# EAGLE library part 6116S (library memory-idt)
MEMORY

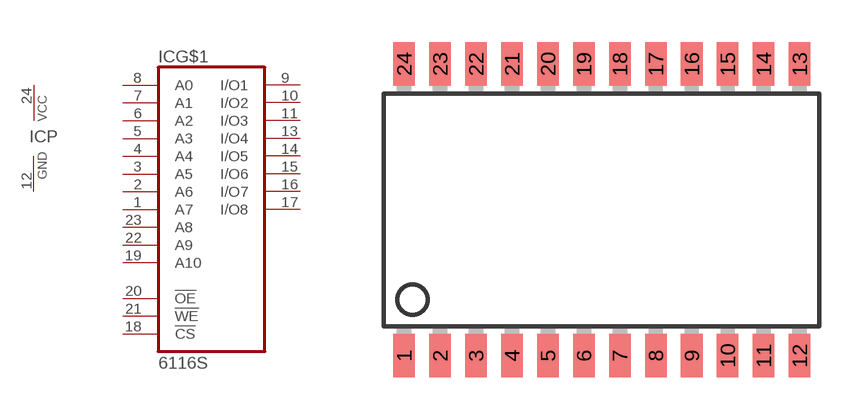
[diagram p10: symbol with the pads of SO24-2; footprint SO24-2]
Designator prefix IC; gates G$1=6116 P=VCCGND

## 6116S (OC_FARNELL: unknown; OC_NEWARK: unknown)  [SO24-2]
1  G$1:A7  in
2  G$1:A6  in
3  G$1:A5  in
4  G$1:A4  in
5  G$1:A3  in
6  G$1:A2  in
7  G$1:A1  in
8  G$1:A0  in
9  G$1:I/O1
10  G$1:I/O2
11  G$1:I/O3
12  P:GND  pwr
13  G$1:I/O4
14  G$1:I/O5
15  G$1:I/O6
16  G$1:I/O7
17  G$1:I/O8
18  G$1:!CS  in
19  G$1:A10  in
20  G$1:!OE  in
21  G$1:!WE  in
22  G$1:A9  in
23  G$1:A8  in
24  P:VCC  pwr

## Footprint SO24-2 (pad centres in mm)
Small Outline Package
smd 0.762 x 1.524: 1 -6.985,-5.156; 2 -5.715,-5.156; 3 -4.445,-5.156; 4 -3.175,-5.156; 5 -1.905,-5.156; 6 -0.635,-5.156; 7 0.635,-5.156; 8 1.905,-5.156; 9 3.175,-5.156; 10 4.445,-5.156; 11 5.715,-5.156; 12 6.985,-5.156; 13 6.985,5.156; 14 5.715,5.156; 15 4.445,5.156; 16 3.175,5.156; 17 1.905,5.156; 18 0.635,5.156; 19 -0.635,5.156; 20 -1.905,5.156; 21 -3.175,5.156; 22 -4.445,5.156; 23 -5.715,5.156; 24 -6.985,5.156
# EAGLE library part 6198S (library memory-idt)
MEMORY

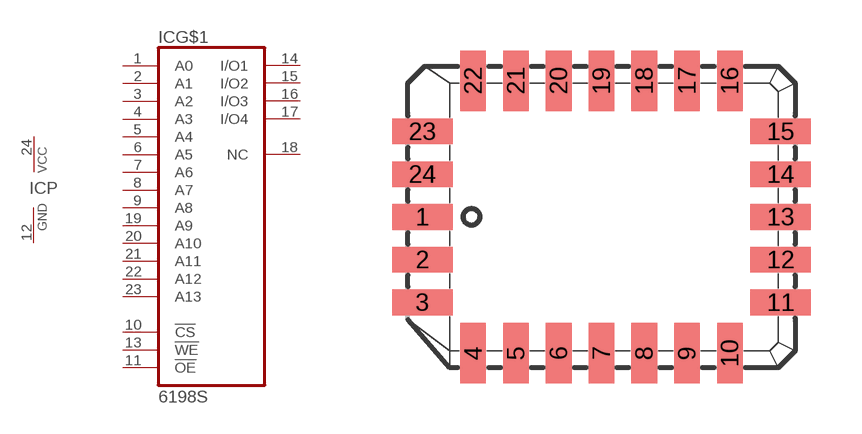
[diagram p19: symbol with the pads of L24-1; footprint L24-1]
Designator prefix IC; gates G$1=6198 P=VCCGND

## 6198S (OC_FARNELL: unknown; OC_NEWARK: unknown)  [L24-1]
1  G$1:A0  in
2  G$1:A1  in
3  G$1:A2  in
4  G$1:A3  in
5  G$1:A4  in
6  G$1:A5  in
7  G$1:A6  in
8  G$1:A7  in
9  G$1:A8  in
10  G$1:!CS  in
11  G$1:!OE  in
12  P:GND  pwr
13  G$1:!WE  in
14  G$1:I/O1
15  G$1:I/O2
16  G$1:I/O3
17  G$1:I/O4
18  G$1:NC  nc
19  G$1:A9  in
20  G$1:A10  in
21  G$1:A11  in
22  G$1:A12  in
23  G$1:A13  in
24  P:VCC  pwr

## Footprint L24-1 (pad centres in mm)
PLASTIC LEADED CHIP CARRIER rectangle
smd 1.8 x 0.76: 1 -5.32,0; 2 -5.32,-1.27; 3 -5.32,-2.54; 11 5.32,-2.54; 12 5.32,-1.27; 13 5.32,0; 14 5.32,1.27; 15 5.32,2.54; 23 -5.32,2.54; 24 -5.32,1.27
smd 0.76 x 1.8: 4 -3.81,-4.05; 5 -2.54,-4.05; 6 -1.27,-4.05; 7 0,-4.05; 8 1.27,-4.05; 9 2.54,-4.05; 10 3.81,-4.05; 16 3.81,4.05; 17 2.54,4.05; 18 1.27,4.05; 19 0,4.05; 20 -1.27,4.05; 21 -2.54,4.05; 22 -3.81,4.05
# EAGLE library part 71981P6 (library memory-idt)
MEMORY

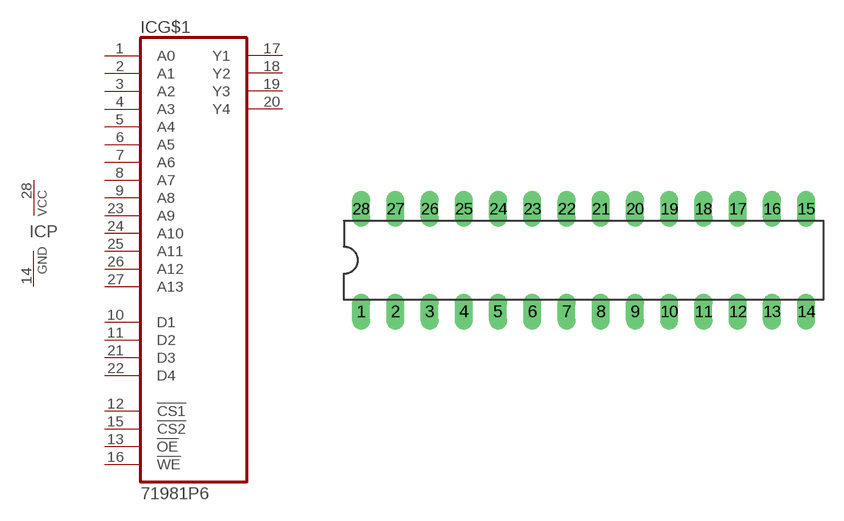
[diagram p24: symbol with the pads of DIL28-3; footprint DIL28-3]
Designator prefix IC; gates G$1=71981 P=VCCGND

## 71981P6 (OC_FARNELL: unknown; OC_NEWARK: unknown)  [DIL28-3]
1  G$1:A0  in
2  G$1:A1  in
3  G$1:A2  in
4  G$1:A3  in
5  G$1:A4  in
6  G$1:A5  in
7  G$1:A6  in
8  G$1:A7  in
9  G$1:A8  in
10  G$1:D1  in
11  G$1:D2  in
12  G$1:!CS1  in
13  G$1:!OE  in
14  P:GND  pwr
15  G$1:!CS2  in
16  G$1:!WE  in
17  G$1:Y1  out
18  G$1:Y2  out
19  G$1:Y3  out
20  G$1:Y4  out
21  G$1:D3  in
22  G$1:D4  in
23  G$1:A9  in
24  G$1:A10  in
25  G$1:A11  in
26  G$1:A12  in
27  G$1:A13  in
28  P:VCC  pwr

## Footprint DIL28-3 (pad centres in mm)
Dual In Line Package Small
drill 0.813 long: 1 -16.51,-3.81; 2 -13.97,-3.81; 3 -11.43,-3.81; 4 -8.89,-3.81; 5 -6.35,-3.81; 6 -3.81,-3.81; 7 -1.27,-3.81; 8 1.27,-3.81; 9 3.81,-3.81; 10 6.35,-3.81; 11 8.89,-3.81; 12 11.43,-3.81; 13 13.97,-3.81; 14 16.51,-3.81; 15 16.51,3.81; 16 13.97,3.81; 17 11.43,3.81; 18 8.89,3.81; 19 6.35,3.81; 20 3.81,3.81; 21 1.27,3.81; 22 -1.27,3.81; 23 -3.81,3.81; 24 -6.35,3.81; 25 -8.89,3.81; 26 -11.43,3.81; 27 -13.97,3.81; 28 -16.51,3.81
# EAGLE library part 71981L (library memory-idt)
MEMORY

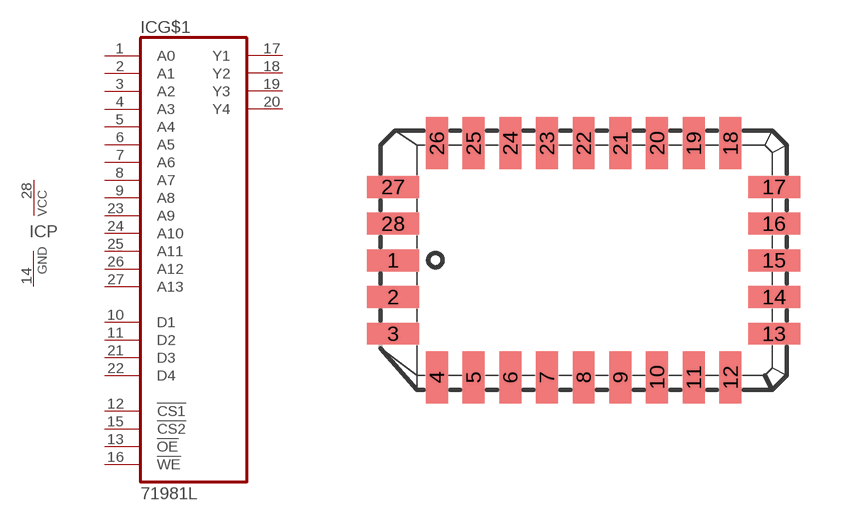
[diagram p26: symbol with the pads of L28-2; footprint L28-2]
Designator prefix IC; gates G$1=71981 P=VCCGND

## 71981L (OC_FARNELL: unknown; OC_NEWARK: unknown)  [L28-2]
1  G$1:A0  in
2  G$1:A1  in
3  G$1:A2  in
4  G$1:A3  in
5  G$1:A4  in
6  G$1:A5  in
7  G$1:A6  in
8  G$1:A7  in
9  G$1:A8  in
10  G$1:D1  in
11  G$1:D2  in
12  G$1:!CS1  in
13  G$1:!OE  in
14  P:GND  pwr
15  G$1:!CS2  in
16  G$1:!WE  in
17  G$1:Y1  out
18  G$1:Y2  out
19  G$1:Y3  out
20  G$1:Y4  out
21  G$1:D3  in
22  G$1:D4  in
23  G$1:A9  in
24  G$1:A10  in
25  G$1:A11  in
26  G$1:A12  in
27  G$1:A13  in
28  P:VCC  pwr

## Footprint L28-2 (pad centres in mm)
PLASTIC LEADED CHIP CARRIER rectangle
smd 1.8 x 0.76: 1 -6.59,0; 2 -6.59,-1.27; 3 -6.59,-2.54; 13 6.59,-2.54; 14 6.59,-1.27; 15 6.59,0; 16 6.59,1.27; 17 6.59,2.54; 27 -6.59,2.54; 28 -6.59,1.27
smd 0.76 x 1.8: 4 -5.08,-4.05; 5 -3.81,-4.05; 6 -2.54,-4.05; 7 -1.27,-4.05; 8 0,-4.05; 9 1.27,-4.05; 10 2.54,-4.05; 11 3.81,-4.05; 12 5.08,-4.05; 18 5.08,4.05; 19 3.81,4.05; 20 2.54,4.05; 21 1.27,4.05; 22 0,4.05; 23 -1.27,4.05; 24 -2.54,4.05; 25 -3.81,4.05; 26 -5.08,4.05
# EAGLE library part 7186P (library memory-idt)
MEMORY

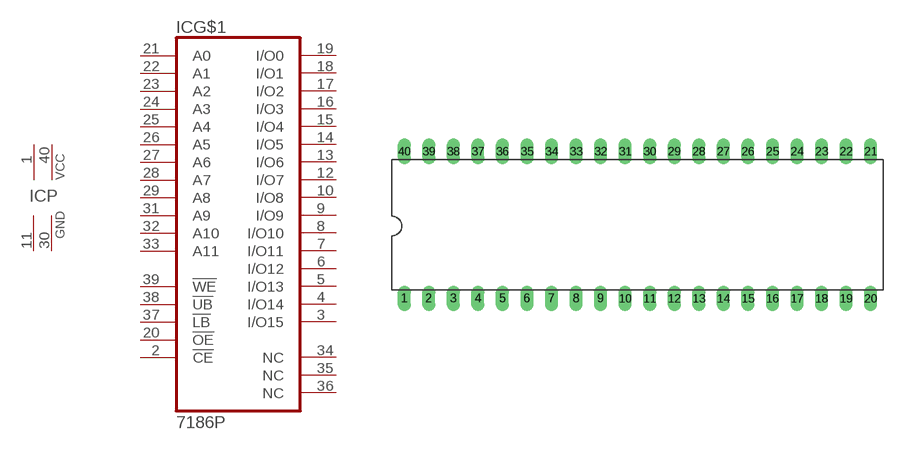
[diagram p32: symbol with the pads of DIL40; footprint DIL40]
Designator prefix IC; gates G$1=7186 P=2VCC2GND

## 7186P (OC_FARNELL: unknown; OC_NEWARK: unknown)  [DIL40]
1  P:VCC  pwr
2  G$1:!CE  in
3  G$1:I/O15
4  G$1:I/O14
5  G$1:I/O13
6  G$1:I/O12
7  G$1:I/O11
8  G$1:I/O10
9  G$1:I/O9
10  G$1:I/O8
11  P:GND  pwr
12  G$1:I/O7
13  G$1:I/O6
14  G$1:I/O5
15  G$1:I/O4
16  G$1:I/O3
17  G$1:I/O2
18  G$1:I/O1
19  G$1:I/O0
20  G$1:!OE  in
21  G$1:A0  in
22  G$1:A1  in
23  G$1:A2  in
24  G$1:A3  in
25  G$1:A4  in
26  G$1:A5  in
27  G$1:A6  in
28  G$1:A7  in
29  G$1:A8  in
30  P:GND  pwr
31  G$1:A9  in
32  G$1:A10  in
33  G$1:A11  in
34  G$1:NC  nc
35  G$1:NC  nc
36  G$1:NC  nc
37  G$1:!LB  in
38  G$1:!UB  in
39  G$1:!WE  in
40  P:VCC  pwr

## Footprint DIL40 (pad centres in mm)
Dual In Line Package
drill 0.813 long: 1 -24.13,-7.62; 2 -21.59,-7.62; 3 -19.05,-7.62; 4 -16.51,-7.62; 5 -13.97,-7.62; 6 -11.43,-7.62; 7 -8.89,-7.62; 8 -6.35,-7.62; 9 -3.81,-7.62; 10 -1.27,-7.62; 11 1.27,-7.62; 12 3.81,-7.62; 13 6.35,-7.62; 14 8.89,-7.62; 15 11.43,-7.62; 16 13.97,-7.62; 17 16.51,-7.62; 18 19.05,-7.62; 19 21.59,-7.62; 20 24.13,-7.62; 21 24.13,7.62; 22 21.59,7.62; 23 19.05,7.62; 24 16.51,7.62; 25 13.97,7.62; 26 11.43,7.62; 27 8.89,7.62; 28 6.35,7.62; 29 3.81,7.62; 30 1.27,7.62; 31 -1.27,7.62; 32 -3.81,7.62; 33 -6.35,7.62; 34 -8.89,7.62; 35 -11.43,7.62; 36 -13.97,7.62; 37 -16.51,7.62; 38 -19.05,7.62; 39 -21.59,7.62; 40 -24.13,7.62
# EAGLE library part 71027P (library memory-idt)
MEMORY

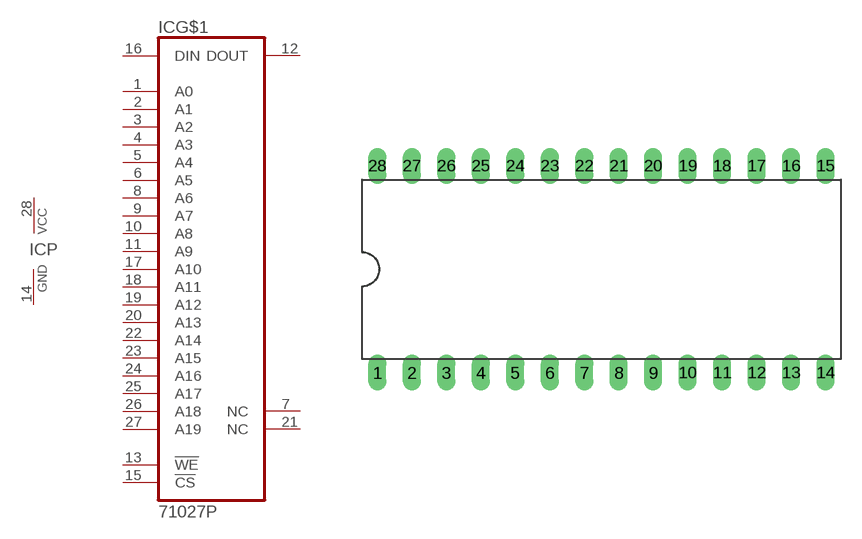
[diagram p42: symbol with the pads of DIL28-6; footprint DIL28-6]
Designator prefix IC; gates G$1=71027 P=VCCGND

## 71027P (OC_FARNELL: unknown; OC_NEWARK: unknown)  [DIL28-6]
1  G$1:A0  in
2  G$1:A1  in
3  G$1:A2  in
4  G$1:A3  in
5  G$1:A4  in
6  G$1:A5  in
7  G$1:NC  nc
8  G$1:A6  in
9  G$1:A7  in
10  G$1:A8  in
11  G$1:A9  in
12  G$1:DOUT  out
13  G$1:!WE  in
14  P:GND  pwr
15  G$1:!CS  in
16  G$1:DIN  in
17  G$1:A10  in
18  G$1:A11  in
19  G$1:A12  in
20  G$1:A13  in
21  G$1:NC  nc
22  G$1:A14  in
23  G$1:A15  in
24  G$1:A16  in
25  G$1:A17  in
26  G$1:A18  in
27  G$1:A19  in
28  P:VCC  pwr

## Footprint DIL28-6 (pad centres in mm)
Dual In Line Package 0.6 inch
drill 0.813 long: 1 -16.51,-7.62; 2 -13.97,-7.62; 3 -11.43,-7.62; 4 -8.89,-7.62; 5 -6.35,-7.62; 6 -3.81,-7.62; 7 -1.27,-7.62; 8 1.27,-7.62; 9 3.81,-7.62; 10 6.35,-7.62; 11 8.89,-7.62; 12 11.43,-7.62; 13 13.97,-7.62; 14 16.51,-7.62; 15 16.51,7.62; 16 13.97,7.62; 17 11.43,7.62; 18 8.89,7.62; 19 6.35,7.62; 20 3.81,7.62; 21 1.27,7.62; 22 -1.27,7.62; 23 -3.81,7.62; 24 -6.35,7.62; 25 -8.89,7.62; 26 -11.43,7.62; 27 -13.97,7.62; 28 -16.51,7.62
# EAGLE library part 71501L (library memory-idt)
MEMORY

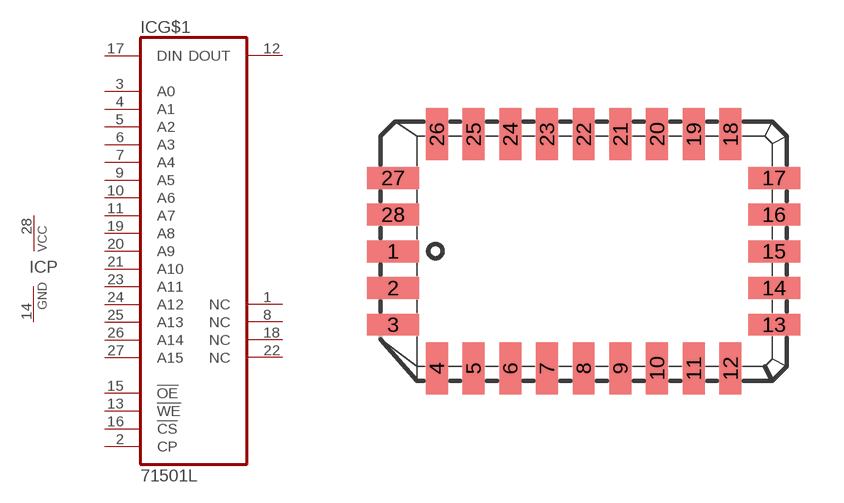
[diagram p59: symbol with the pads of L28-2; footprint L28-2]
Designator prefix IC; gates G$1=71501L P=VCCGND

## 71501L (OC_FARNELL: unknown; OC_NEWARK: unknown)  [L28-2]
1  G$1:NC  nc
2  G$1:CP  in
3  G$1:A0  in
4  G$1:A1  in
5  G$1:A2  in
6  G$1:A3  in
7  G$1:A4  in
8  G$1:NC  nc
9  G$1:A5  in
10  G$1:A6  in
11  G$1:A7  in
12  G$1:DOUT  out
13  G$1:!WE  in
14  P:GND  pwr
15  G$1:!OE  in
16  G$1:!CS  in
17  G$1:DIN  in
18  G$1:NC  nc
19  G$1:A8  in
20  G$1:A9  in
21  G$1:A10  in
22  G$1:NC  nc
23  G$1:A11  in
24  G$1:A12  in
25  G$1:A13  in
26  G$1:A14  in
27  G$1:A15  in
28  P:VCC  pwr

## Footprint L28-2 (pad centres in mm)
PLASTIC LEADED CHIP CARRIER rectangle
smd 1.8 x 0.76: 1 -6.59,0; 2 -6.59,-1.27; 3 -6.59,-2.54; 13 6.59,-2.54; 14 6.59,-1.27; 15 6.59,0; 16 6.59,1.27; 17 6.59,2.54; 27 -6.59,2.54; 28 -6.59,1.27
smd 0.76 x 1.8: 4 -5.08,-4.05; 5 -3.81,-4.05; 6 -2.54,-4.05; 7 -1.27,-4.05; 8 0,-4.05; 9 1.27,-4.05; 10 2.54,-4.05; 11 3.81,-4.05; 12 5.08,-4.05; 18 5.08,4.05; 19 3.81,4.05; 20 2.54,4.05; 21 1.27,4.05; 22 0,4.05; 23 -1.27,4.05; 24 -2.54,4.05; 25 -3.81,4.05; 26 -5.08,4.05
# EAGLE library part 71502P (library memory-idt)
MEMORY

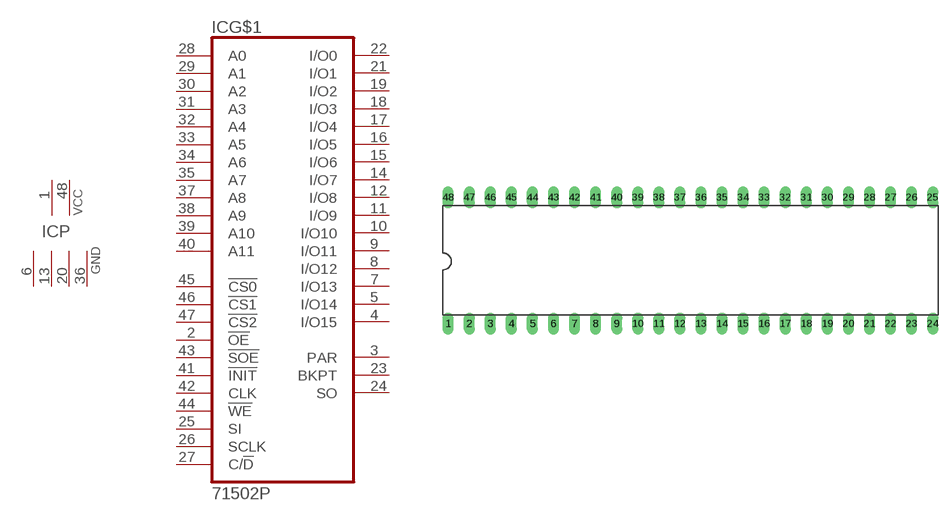
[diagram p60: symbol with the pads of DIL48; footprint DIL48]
Designator prefix IC; gates G$1=71502 P=2VCC4GND

## 71502P (OC_FARNELL: unknown; OC_NEWARK: unknown)  [DIL48]
1  P:VCC  pwr
2  G$1:!OE  in
3  G$1:PAR  out
4  G$1:I/O15
5  G$1:I/O14
6  P:GND  pwr
7  G$1:I/O13
8  G$1:I/O12
9  G$1:I/O11
10  G$1:I/O10
11  G$1:I/O9
12  G$1:I/O8
13  P:GND  pwr
14  G$1:I/O7
15  G$1:I/O6
16  G$1:I/O5
17  G$1:I/O4
18  G$1:I/O3
19  G$1:I/O2
20  P:GND  pwr
21  G$1:I/O1
22  G$1:I/O0
23  G$1:BKPT  out
24  G$1:SO  out
25  G$1:SI  in
26  G$1:SCLK  in
27  G$1:C/!D  in
28  G$1:A0  in
29  G$1:A1  in
30  G$1:A2  in
31  G$1:A3  in
32  G$1:A4  in
33  G$1:A5  in
34  G$1:A6  in
35  G$1:A7  in
36  P:GND  pwr
37  G$1:A8  in
38  G$1:A9  in
39  G$1:A10  in
40  G$1:A11  in
41  G$1:!INIT  in
42  G$1:CLK  in
43  G$1:!SOE  in
44  G$1:!WE  in
45  G$1:!CS0  in
46  G$1:!CS1  in
47  G$1:!CS2  in
48  P:VCC  pwr

## Footprint DIL48 (pad centres in mm)
Dual In Line Package
drill 0.813 long: 1 -29.21,-7.62; 2 -26.67,-7.62; 3 -24.13,-7.62; 4 -21.59,-7.62; 5 -19.05,-7.62; 6 -16.51,-7.62; 7 -13.97,-7.62; 8 -11.43,-7.62; 9 -8.89,-7.62; 10 -6.35,-7.62; 11 -3.81,-7.62; 12 -1.27,-7.62; 13 1.27,-7.62; 14 3.81,-7.62; 15 6.35,-7.62; 16 8.89,-7.62; 17 11.43,-7.62; 18 13.97,-7.62; 19 16.51,-7.62; 20 19.05,-7.62; 21 21.59,-7.62; 22 24.13,-7.62; 23 26.67,-7.62; 24 29.21,-7.62; 25 29.21,7.62; 26 26.67,7.62; 27 24.13,7.62; 28 21.59,7.62; 29 19.05,7.62; 30 16.51,7.62; 31 13.97,7.62; 32 11.43,7.62; 33 8.89,7.62; 34 6.35,7.62; 35 3.81,7.62; 36 1.27,7.62; 37 -1.27,7.62; 38 -3.81,7.62; 39 -6.35,7.62; 40 -8.89,7.62; 41 -11.43,7.62; 42 -13.97,7.62; 43 -16.51,7.62; 44 -19.05,7.62; 45 -21.59,7.62; 46 -24.13,7.62; 47 -26.67,7.62; 48 -29.21,7.62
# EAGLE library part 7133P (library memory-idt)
MEMORY

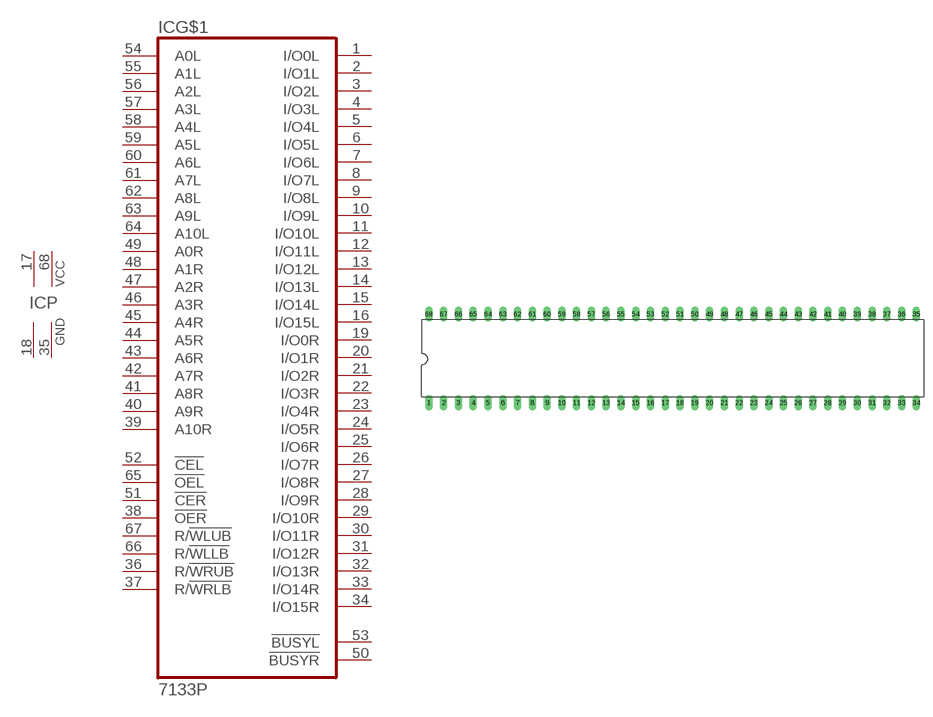
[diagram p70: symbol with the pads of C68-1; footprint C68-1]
Designator prefix IC; gates G$1=7133 P=2VCC2GND

## 7133P (OC_FARNELL: unknown; OC_NEWARK: unknown)  [C68-1]
1  G$1:I/O0L
2  G$1:I/O1L
3  G$1:I/O2L
4  G$1:I/O3L
5  G$1:I/O4L
6  G$1:I/O5L
7  G$1:I/O6L
8  G$1:I/O7L
9  G$1:I/O8L
10  G$1:I/O9L
11  G$1:I/O10L
12  G$1:I/O11L
13  G$1:I/O12L
14  G$1:I/O13L
15  G$1:I/O14L
16  G$1:I/O15L
17  P:VCC  pwr
18  P:GND  pwr
19  G$1:I/O0R
20  G$1:I/O1R
21  G$1:I/O2R
22  G$1:I/O3R
23  G$1:I/O4R
24  G$1:I/O5R
25  G$1:I/O6R
26  G$1:I/O7R
27  G$1:I/O8R
28  G$1:I/O9R
29  G$1:I/O10R
30  G$1:I/O11R
31  G$1:I/O12R
32  G$1:I/O13R
33  G$1:I/O14R
34  G$1:I/O15R
35  P:GND  pwr
36  G$1:R/!WRUB  in
37  G$1:R/!WRLB  in
38  G$1:!OER  in
39  G$1:A10R  in
40  G$1:A9R  in
41  G$1:A8R  in
42  G$1:A7R  in
43  G$1:A6R  in
44  G$1:A5R  in
45  G$1:A4R  in
46  G$1:A3R  in
47  G$1:A2R  in
48  G$1:A1R  in
49  G$1:A0R  in
50  G$1:!BUSYR  out
51  G$1:!CER  in
52  G$1:!CEL  in
53  G$1:!BUSYL  out
54  G$1:A0L  in
55  G$1:A1L  in
56  G$1:A2L  in
57  G$1:A3L  in
58  G$1:A4L  in
59  G$1:A5L  in
60  G$1:A6L  in
61  G$1:A7L  in
62  G$1:A8L  in
63  G$1:A9L  in
64  G$1:A10L  in
65  G$1:!OEL  in
66  G$1:R/!WLLB  in
67  G$1:R/!WLUB  in
68  P:VCC  pwr

## Footprint C68-1 (pad centres in mm)
Dual In Line
drill 0.813 long: 1 -41.91,-7.62; 2 -39.37,-7.62; 3 -36.83,-7.62; 4 -34.29,-7.62; 5 -31.75,-7.62; 6 -29.21,-7.62; 7 -26.67,-7.62; 8 -24.13,-7.62; 9 -21.59,-7.62; 10 -19.05,-7.62; 11 -16.51,-7.62; 12 -13.97,-7.62; 13 -11.43,-7.62; 14 -8.89,-7.62; 15 -6.35,-7.62; 16 -3.81,-7.62; 17 -1.27,-7.62; 18 1.27,-7.62; 19 3.81,-7.62; 20 6.35,-7.62; 21 8.89,-7.62; 22 11.43,-7.62; 23 13.97,-7.62; 24 16.51,-7.62; 25 19.05,-7.62; 26 21.59,-7.62; 27 24.13,-7.62; 28 26.67,-7.62; 29 29.21,-7.62; 30 31.75,-7.62; 31 34.29,-7.62; 32 36.83,-7.62; 33 39.37,-7.62; 34 41.91,-7.62; 35 41.91,7.62; 36 39.37,7.62; 37 36.83,7.62; 38 34.29,7.62; 39 31.75,7.62; 40 29.21,7.62; 41 26.67,7.62; 42 24.13,7.62; 43 21.59,7.62; 44 19.05,7.62; 45 16.51,7.62; 46 13.97,7.62; 47 11.43,7.62; 48 8.89,7.62; 49 6.35,7.62; 50 3.81,7.62; 51 1.27,7.62; 52 -1.27,7.62; 53 -3.81,7.62; 54 -6.35,7.62; 55 -8.89,7.62; 56 -11.43,7.62; 57 -13.97,7.62; 58 -16.51,7.62; 59 -19.05,7.62; 60 -21.59,7.62; 61 -24.13,7.62; 62 -26.67,7.62; 63 -29.21,7.62; 64 -31.75,7.62; 65 -34.29,7.62; 66 -36.83,7.62; 67 -39.37,7.62; 68 -41.91,7.62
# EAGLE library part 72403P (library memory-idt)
MEMORY

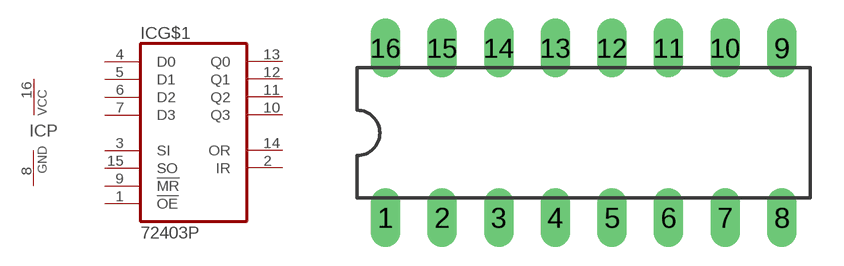
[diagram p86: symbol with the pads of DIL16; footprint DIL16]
Designator prefix IC; gates G$1=72403 P=VCCGND

## 72403P (OC_FARNELL: unknown; OC_NEWARK: unknown)  [DIL16]
1  G$1:!OE  in
2  G$1:IR  out
3  G$1:SI  in
4  G$1:D0  in
5  G$1:D1  in
6  G$1:D2  in
7  G$1:D3  in
8  P:GND  pwr
9  G$1:!MR  in
10  G$1:Q3  out
11  G$1:Q2  out
12  G$1:Q1  out
13  G$1:Q0  out
14  G$1:OR  out
15  G$1:SO  in
16  P:VCC  pwr

## Footprint DIL16 (pad centres in mm)
Dual In Line Package
drill 0.813 long: 1 -8.89,-3.81; 2 -6.35,-3.81; 3 -3.81,-3.81; 4 -1.27,-3.81; 5 1.27,-3.81; 6 3.81,-3.81; 7 6.35,-3.81; 8 8.89,-3.81; 9 8.89,3.81; 10 6.35,3.81; 11 3.81,3.81; 12 1.27,3.81; 13 -1.27,3.81; 14 -3.81,3.81; 15 -6.35,3.81; 16 -8.89,3.81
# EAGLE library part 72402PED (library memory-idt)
MEMORY

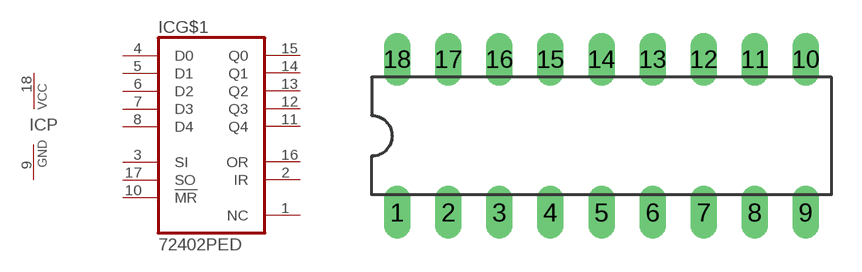
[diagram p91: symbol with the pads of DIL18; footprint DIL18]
Designator prefix IC; gates G$1=72402 P=VCCGND

## 72402PED (OC_FARNELL: unknown; OC_NEWARK: unknown)  [DIL18]
1  G$1:NC  nc
2  G$1:IR  out
3  G$1:SI  in
4  G$1:D0  in
5  G$1:D1  in
6  G$1:D2  in
7  G$1:D3  in
8  G$1:D4  in
9  P:GND  pwr
10  G$1:!MR  in
11  G$1:Q4  out
12  G$1:Q3  out
13  G$1:Q2  out
14  G$1:Q1  out
15  G$1:Q0  out
16  G$1:OR  out
17  G$1:SO  in
18  P:VCC  pwr

## Footprint DIL18 (pad centres in mm)
Dual In Line Package
drill 0.813 long: 1 -10.16,-3.81; 2 -7.62,-3.81; 3 -5.08,-3.81; 4 -2.54,-3.81; 5 0,-3.81; 6 2.54,-3.81; 7 5.08,-3.81; 8 7.62,-3.81; 9 10.16,-3.81; 10 10.16,3.81; 11 7.62,3.81; 12 5.08,3.81; 13 2.54,3.81; 14 0,3.81; 15 -2.54,3.81; 16 -5.08,3.81; 17 -7.62,3.81; 18 -10.16,3.81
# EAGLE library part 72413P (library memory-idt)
MEMORY

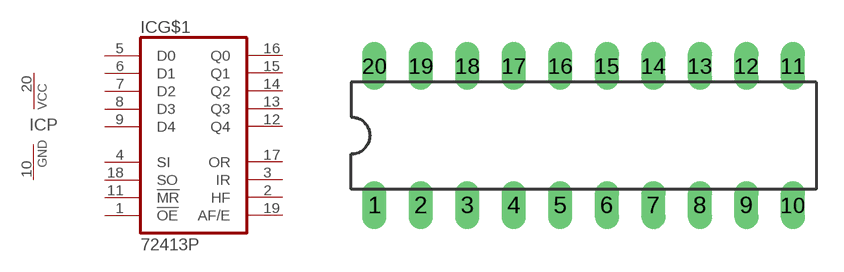
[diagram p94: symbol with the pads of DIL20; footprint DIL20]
Designator prefix IC; gates G$1=72413 P=VCCGND

## 72413P (OC_FARNELL: unknown; OC_NEWARK: unknown)  [DIL20]
1  G$1:!OE  in
2  G$1:HF  out
3  G$1:IR  out
4  G$1:SI  in
5  G$1:D0  in
6  G$1:D1  in
7  G$1:D2  in
8  G$1:D3  in
9  G$1:D4  in
10  P:GND  pwr
11  G$1:!MR  in
12  G$1:Q4  out
13  G$1:Q3  out
14  G$1:Q2  out
15  G$1:Q1  out
16  G$1:Q0  out
17  G$1:OR  out
18  G$1:SO  in
19  G$1:AF/E  out
20  P:VCC  pwr

## Footprint DIL20 (pad centres in mm)
Dual In Line Package
drill 0.813 long: 1 -11.43,-3.81; 2 -8.89,-3.81; 3 -6.35,-3.81; 4 -3.81,-3.81; 5 -1.27,-3.81; 6 1.27,-3.81; 7 3.81,-3.81; 8 6.35,-3.81; 9 8.89,-3.81; 10 11.43,-3.81; 11 11.43,3.81; 12 8.89,3.81; 13 6.35,3.81; 14 3.81,3.81; 15 1.27,3.81; 16 -1.27,3.81; 17 -3.81,3.81; 18 -6.35,3.81; 19 -8.89,3.81; 20 -11.43,3.81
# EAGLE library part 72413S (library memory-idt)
MEMORY

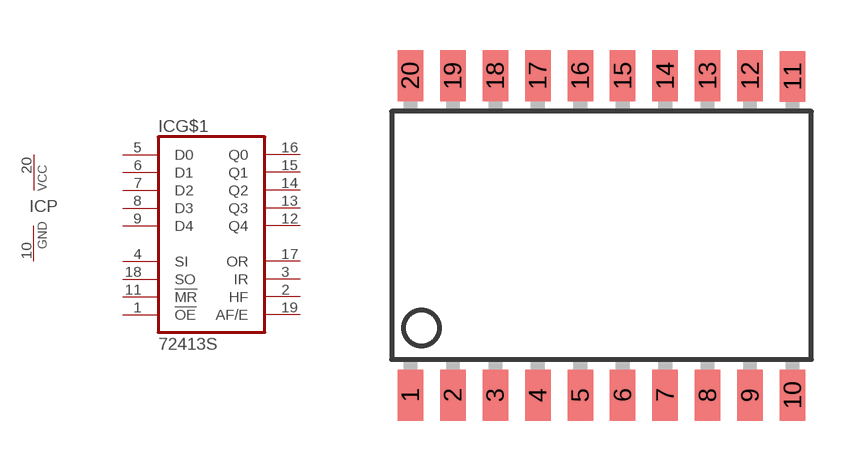
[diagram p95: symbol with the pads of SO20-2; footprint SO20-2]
Designator prefix IC; gates G$1=72413 P=VCCGND

## 72413S (OC_FARNELL: unknown; OC_NEWARK: unknown)  [SO20-2]
1  G$1:!OE  in
2  G$1:HF  out
3  G$1:IR  out
4  G$1:SI  in
5  G$1:D0  in
6  G$1:D1  in
7  G$1:D2  in
8  G$1:D3  in
9  G$1:D4  in
10  P:GND  pwr
11  G$1:!MR  in
12  G$1:Q4  out
13  G$1:Q3  out
14  G$1:Q2  out
15  G$1:Q1  out
16  G$1:Q0  out
17  G$1:OR  out
18  G$1:SO  in
19  G$1:AF/E  out
20  P:VCC  pwr

## Footprint SO20-2 (pad centres in mm)
Small Outline Package
smd 0.762 x 1.524: 1 -5.715,-4.775; 2 -4.445,-4.775; 3 -3.175,-4.775; 4 -1.905,-4.775; 5 -0.635,-4.775; 6 0.635,-4.775; 7 1.905,-4.775; 8 3.175,-4.775; 9 4.445,-4.775; 10 5.715,-4.775; 11 5.715,4.75; 12 4.445,4.775; 13 3.175,4.775; 14 1.905,4.775; 15 0.635,4.775; 16 -0.635,4.775; 17 -1.905,4.775; 18 -3.175,4.775; 19 -4.445,4.775; 20 -5.715,4.775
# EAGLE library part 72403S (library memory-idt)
MEMORY

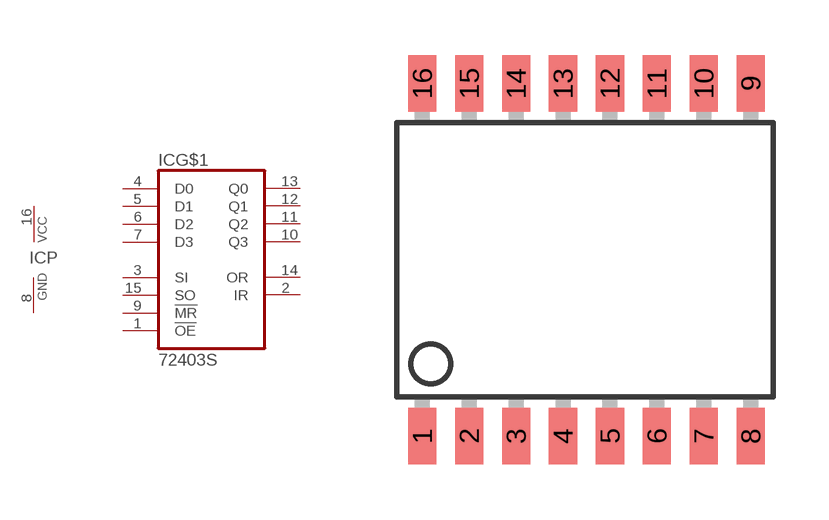
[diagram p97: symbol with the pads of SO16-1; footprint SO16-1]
Designator prefix IC; gates G$1=72403 P=VCCGND

## 72403S (OC_FARNELL: unknown; OC_NEWARK: unknown)  [SO16-1]
1  G$1:!OE  in
2  G$1:IR  out
3  G$1:SI  in
4  G$1:D0  in
5  G$1:D1  in
6  G$1:D2  in
7  G$1:D3  in
8  P:GND  pwr
9  G$1:!MR  in
10  G$1:Q3  out
11  G$1:Q2  out
12  G$1:Q1  out
13  G$1:Q0  out
14  G$1:OR  out
15  G$1:SO  in
16  P:VCC  pwr

## Footprint SO16-1 (pad centres in mm)
Small Outline Package
smd 0.762 x 1.524: 1 -4.445,-4.775; 2 -3.175,-4.775; 3 -1.905,-4.775; 4 -0.635,-4.775; 5 0.635,-4.775; 6 1.905,-4.775; 7 3.175,-4.775; 8 4.445,-4.775; 9 4.445,4.775; 10 3.175,4.775; 11 1.905,4.775; 12 0.635,4.775; 13 -0.635,4.775; 14 -1.905,4.775; 15 -3.175,4.775; 16 -4.445,4.775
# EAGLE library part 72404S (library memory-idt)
MEMORY

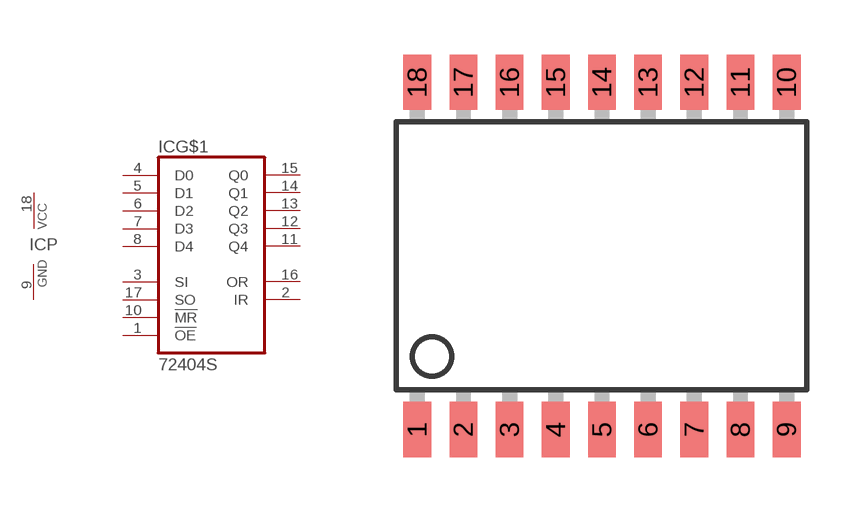
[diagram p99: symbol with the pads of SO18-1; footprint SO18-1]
Designator prefix IC; gates G$1=72404 P=VCCGND

## 72404S (OC_FARNELL: unknown; OC_NEWARK: unknown)  [SO18-1]
1  G$1:!OE  in
2  G$1:IR  out
3  G$1:SI  in
4  G$1:D0  in
5  G$1:D1  in
6  G$1:D2  in
7  G$1:D3  in
8  G$1:D4  in
9  P:GND  pwr
10  G$1:!MR  in
11  G$1:Q4  out
12  G$1:Q3  out
13  G$1:Q2  out
14  G$1:Q1  out
15  G$1:Q0  out
16  G$1:OR  out
17  G$1:SO  in
18  P:VCC  pwr

## Footprint SO18-1 (pad centres in mm)
Small Outline Package
smd 0.762 x 1.524: 1 -5.08,-4.775; 2 -3.81,-4.775; 3 -2.54,-4.775; 4 -1.27,-4.775; 5 0,-4.775; 6 1.27,-4.775; 7 2.54,-4.775; 8 3.81,-4.775; 9 5.08,-4.775; 10 5.08,4.775; 11 3.81,4.775; 12 2.54,4.775; 13 1.27,4.775; 14 0,4.775; 15 -1.27,4.775; 16 -2.54,4.775; 17 -3.81,4.775; 18 -5.08,4.775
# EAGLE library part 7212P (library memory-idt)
MEMORY

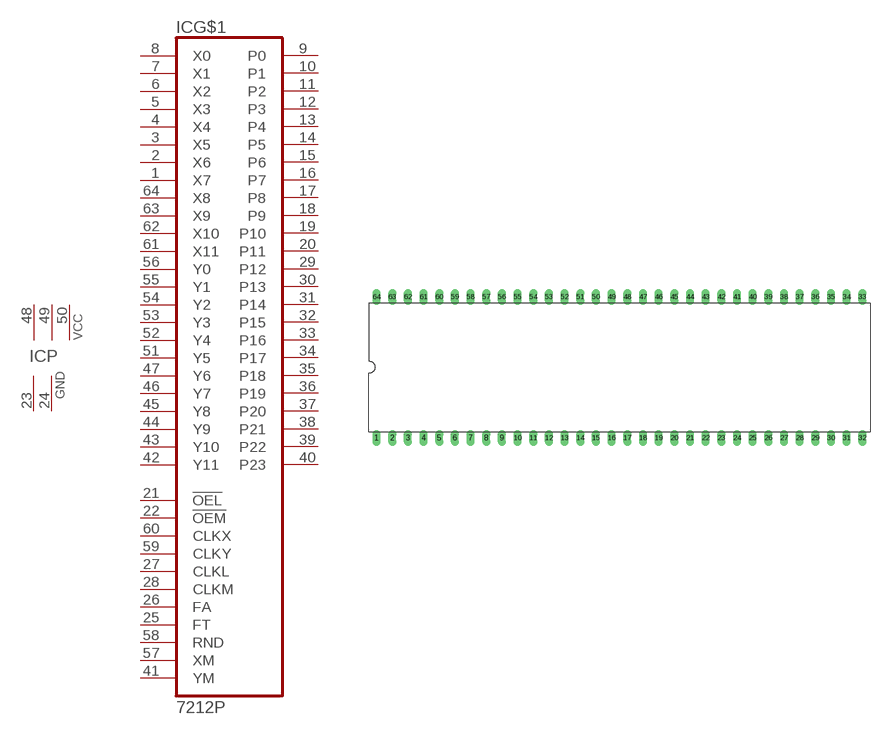
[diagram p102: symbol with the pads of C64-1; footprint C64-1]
Designator prefix IC; gates G$1=7212 P=3VCC2GND

## 7212P (OC_FARNELL: unknown; OC_NEWARK: unknown)  [C64-1]
1  G$1:X7  in
2  G$1:X6  in
3  G$1:X5  in
4  G$1:X4  in
5  G$1:X3  in
6  G$1:X2  in
7  G$1:X1  in
8  G$1:X0  in
9  G$1:P0  out
10  G$1:P1  out
11  G$1:P2  out
12  G$1:P3  out
13  G$1:P4  out
14  G$1:P5  out
15  G$1:P6  out
16  G$1:P7  out
17  G$1:P8  out
18  G$1:P9  out
19  G$1:P10  out
20  G$1:P11  out
21  G$1:!OEL  in
22  G$1:!OEM  in
23  P:GND  pwr
24  P:GND  pwr
25  G$1:FT  in
26  G$1:FA  in
27  G$1:CLKL  in
28  G$1:CLKM  in
29  G$1:P12  out
30  G$1:P13  out
31  G$1:P14  out
32  G$1:P15  out
33  G$1:P16  out
34  G$1:P17  out
35  G$1:P18  out
36  G$1:P19  out
37  G$1:P20  out
38  G$1:P21  out
39  G$1:P22  out
40  G$1:P23  out
41  G$1:YM  in
42  G$1:Y11  in
43  G$1:Y10  in
44  G$1:Y9  in
45  G$1:Y8  in
46  G$1:Y7  in
47  G$1:Y6  in
48  P:VCC  pwr
49  P:VCC  pwr
50  P:VCC  pwr
51  G$1:Y5  in
52  G$1:Y4  in
53  G$1:Y3  in
54  G$1:Y2  in
55  G$1:Y1  in
56  G$1:Y0  in
57  G$1:XM  in
58  G$1:RND  in
59  G$1:CLKY  in
60  G$1:CLKX  in
61  G$1:X11  in
62  G$1:X10  in
63  G$1:X9  in
64  G$1:X8  in

## Footprint C64-1 (pad centres in mm)
Dual In Line
drill 0.813 long: 1 -39.37,-11.43; 2 -36.83,-11.43; 3 -34.29,-11.43; 4 -31.75,-11.43; 5 -29.21,-11.43; 6 -26.67,-11.43; 7 -24.13,-11.43; 8 -21.59,-11.43; 9 -19.05,-11.43; 10 -16.51,-11.43; 11 -13.97,-11.43; 12 -11.43,-11.43; 13 -8.89,-11.43; 14 -6.35,-11.43; 15 -3.81,-11.43; 16 -1.27,-11.43; 17 1.27,-11.43; 18 3.81,-11.43; 19 6.35,-11.43; 20 8.89,-11.43; 21 11.43,-11.43; 22 13.97,-11.43; 23 16.51,-11.43; 24 19.05,-11.43; 25 21.59,-11.43; 26 24.13,-11.43; 27 26.67,-11.43; 28 29.21,-11.43; 29 31.75,-11.43; 30 34.29,-11.43; 31 36.83,-11.43; 32 39.37,-11.43; 33 39.37,11.43; 34 36.83,11.43; 35 34.29,11.43; 36 31.75,11.43; 37 29.21,11.43; 38 26.67,11.43; 39 24.13,11.43; 40 21.59,11.43; 41 19.05,11.43; 42 16.51,11.43; 43 13.97,11.43; 44 11.43,11.43; 45 8.89,11.43; 46 6.35,11.43; 47 3.81,11.43; 48 1.27,11.43; 49 -1.27,11.43; 50 -3.81,11.43; 51 -6.35,11.43; 52 -8.89,11.43; 53 -11.43,11.43; 54 -13.97,11.43; 55 -16.51,11.43; 56 -19.05,11.43; 57 -21.59,11.43; 58 -24.13,11.43; 59 -26.67,11.43; 60 -29.21,11.43; 61 -31.75,11.43; 62 -34.29,11.43; 63 -36.83,11.43; 64 -39.37,11.43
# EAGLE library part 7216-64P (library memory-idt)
MEMORY

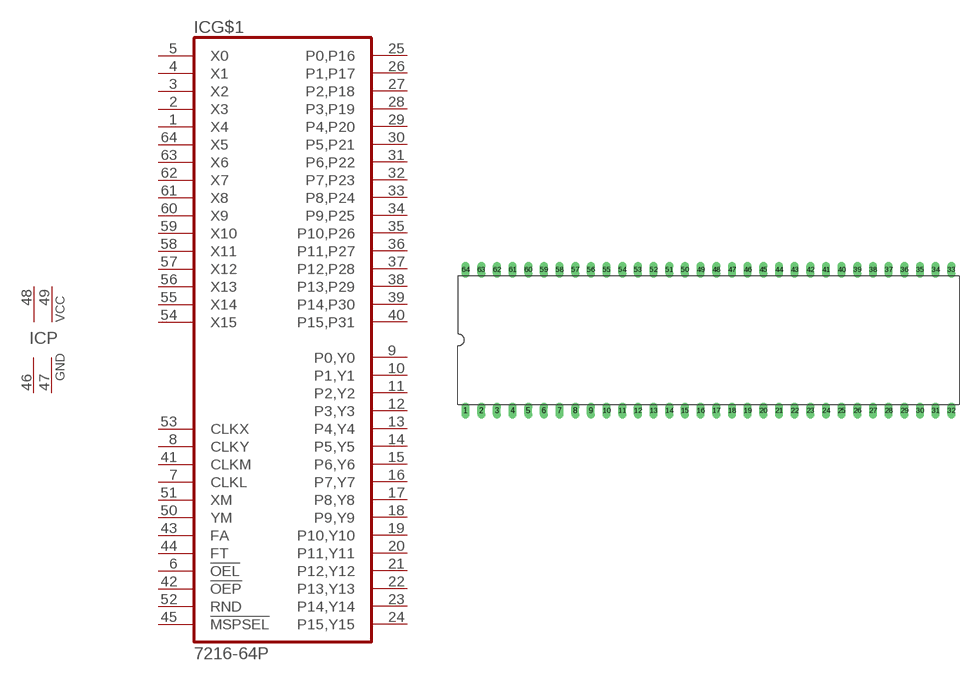
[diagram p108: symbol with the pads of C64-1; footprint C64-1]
Designator prefix IC; gates G$1=7216-64 P=2VCC2GND

## 7216-64P (OC_FARNELL: unknown; OC_NEWARK: unknown)  [C64-1]
1  G$1:X4  in
2  G$1:X3  in
3  G$1:X2  in
4  G$1:X1  in
5  G$1:X0  in
6  G$1:!OEL  in
7  G$1:CLKL  in
8  G$1:CLKY  in
9  G$1:P0,Y0
10  G$1:P1,Y1
11  G$1:P2,Y2
12  G$1:P3,Y3
13  G$1:P4,Y4
14  G$1:P5,Y5
15  G$1:P6,Y6
16  G$1:P7,Y7
17  G$1:P8,Y8
18  G$1:P9,Y9
19  G$1:P10,Y10
20  G$1:P11,Y11
21  G$1:P12,Y12
22  G$1:P13,Y13
23  G$1:P14,Y14
24  G$1:P15,Y15
25  G$1:P0,P16  out
26  G$1:P1,P17  out
27  G$1:P2,P18  out
28  G$1:P3,P19  out
29  G$1:P4,P20  out
30  G$1:P5,P21  out
31  G$1:P6,P22  out
32  G$1:P7,P23  out
33  G$1:P8,P24  out
34  G$1:P9,P25  out
35  G$1:P10,P26  out
36  G$1:P11,P27  out
37  G$1:P12,P28  out
38  G$1:P13,P29  out
39  G$1:P14,P30  out
40  G$1:P15,P31  out
41  G$1:CLKM  in
42  G$1:!OEP  in
43  G$1:FA  in
44  G$1:FT  in
45  G$1:!MSPSEL  in
46  P:GND  pwr
47  P:GND  pwr
48  P:VCC  pwr
49  P:VCC  pwr
50  G$1:YM  in
51  G$1:XM  in
52  G$1:RND  in
53  G$1:CLKX  in
54  G$1:X15  in
55  G$1:X14  in
56  G$1:X13  in
57  G$1:X12  in
58  G$1:X11  in
59  G$1:X10  in
60  G$1:X9  in
61  G$1:X8  in
62  G$1:X7  in
63  G$1:X6  in
64  G$1:X5  in

## Footprint C64-1 (pad centres in mm)
Dual In Line
drill 0.813 long: 1 -39.37,-11.43; 2 -36.83,-11.43; 3 -34.29,-11.43; 4 -31.75,-11.43; 5 -29.21,-11.43; 6 -26.67,-11.43; 7 -24.13,-11.43; 8 -21.59,-11.43; 9 -19.05,-11.43; 10 -16.51,-11.43; 11 -13.97,-11.43; 12 -11.43,-11.43; 13 -8.89,-11.43; 14 -6.35,-11.43; 15 -3.81,-11.43; 16 -1.27,-11.43; 17 1.27,-11.43; 18 3.81,-11.43; 19 6.35,-11.43; 20 8.89,-11.43; 21 11.43,-11.43; 22 13.97,-11.43; 23 16.51,-11.43; 24 19.05,-11.43; 25 21.59,-11.43; 26 24.13,-11.43; 27 26.67,-11.43; 28 29.21,-11.43; 29 31.75,-11.43; 30 34.29,-11.43; 31 36.83,-11.43; 32 39.37,-11.43; 33 39.37,11.43; 34 36.83,11.43; 35 34.29,11.43; 36 31.75,11.43; 37 29.21,11.43; 38 26.67,11.43; 39 24.13,11.43; 40 21.59,11.43; 41 19.05,11.43; 42 16.51,11.43; 43 13.97,11.43; 44 11.43,11.43; 45 8.89,11.43; 46 6.35,11.43; 47 3.81,11.43; 48 1.27,11.43; 49 -1.27,11.43; 50 -3.81,11.43; 51 -6.35,11.43; 52 -8.89,11.43; 53 -11.43,11.43; 54 -13.97,11.43; 55 -16.51,11.43; 56 -19.05,11.43; 57 -21.59,11.43; 58 -24.13,11.43; 59 -26.67,11.43; 60 -29.21,11.43; 61 -31.75,11.43; 62 -34.29,11.43; 63 -36.83,11.43; 64 -39.37,11.43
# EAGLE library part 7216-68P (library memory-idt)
MEMORY

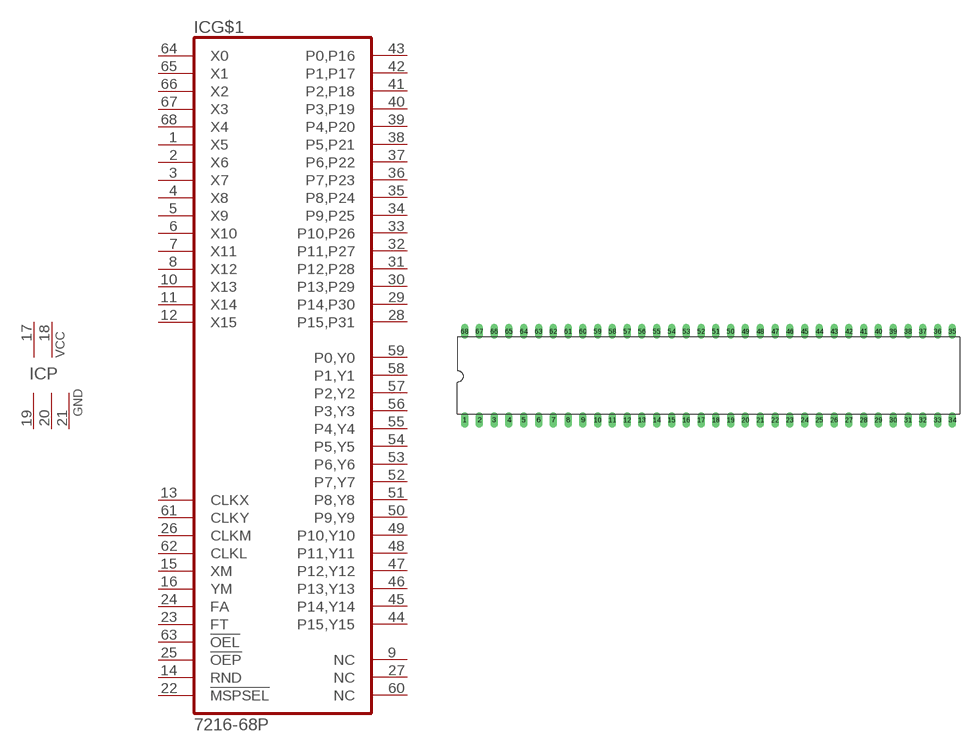
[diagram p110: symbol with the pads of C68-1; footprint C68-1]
Designator prefix IC; gates G$1=7216-68 P=2VCC3GND

## 7216-68P (OC_FARNELL: unknown; OC_NEWARK: unknown)  [C68-1]
1  G$1:X5  in
2  G$1:X6  in
3  G$1:X7  in
4  G$1:X8  in
5  G$1:X9  in
6  G$1:X10  in
7  G$1:X11  in
8  G$1:X12  in
9  G$1:NC  nc
10  G$1:X13  in
11  G$1:X14  in
12  G$1:X15  in
13  G$1:CLKX  in
14  G$1:RND  in
15  G$1:XM  in
16  G$1:YM  in
17  P:VCC  pwr
18  P:VCC  pwr
19  P:GND  pwr
20  P:GND  pwr
21  P:GND  pwr
22  G$1:!MSPSEL  in
23  G$1:FT  in
24  G$1:FA  in
25  G$1:!OEP  in
26  G$1:CLKM  in
27  G$1:NC  nc
28  G$1:P15,P31  out
29  G$1:P14,P30  out
30  G$1:P13,P29  out
31  G$1:P12,P28  out
32  G$1:P11,P27  out
33  G$1:P10,P26  out
34  G$1:P9,P25  out
35  G$1:P8,P24  out
36  G$1:P7,P23  out
37  G$1:P6,P22  out
38  G$1:P5,P21  out
39  G$1:P4,P20  out
40  G$1:P3,P19  out
41  G$1:P2,P18  out
42  G$1:P1,P17  out
43  G$1:P0,P16  out
44  G$1:P15,Y15
45  G$1:P14,Y14
46  G$1:P13,Y13
47  G$1:P12,Y12
48  G$1:P11,Y11
49  G$1:P10,Y10
50  G$1:P9,Y9
51  G$1:P8,Y8
52  G$1:P7,Y7
53  G$1:P6,Y6
54  G$1:P5,Y5
55  G$1:P4,Y4
56  G$1:P3,Y3
57  G$1:P2,Y2
58  G$1:P1,Y1
59  G$1:P0,Y0
60  G$1:NC  nc
61  G$1:CLKY  in
62  G$1:CLKL  in
63  G$1:!OEL  in
64  G$1:X0  in
65  G$1:X1  in
66  G$1:X2  in
67  G$1:X3  in
68  G$1:X4  in

## Footprint C68-1 (pad centres in mm)
Dual In Line
drill 0.813 long: 1 -41.91,-7.62; 2 -39.37,-7.62; 3 -36.83,-7.62; 4 -34.29,-7.62; 5 -31.75,-7.62; 6 -29.21,-7.62; 7 -26.67,-7.62; 8 -24.13,-7.62; 9 -21.59,-7.62; 10 -19.05,-7.62; 11 -16.51,-7.62; 12 -13.97,-7.62; 13 -11.43,-7.62; 14 -8.89,-7.62; 15 -6.35,-7.62; 16 -3.81,-7.62; 17 -1.27,-7.62; 18 1.27,-7.62; 19 3.81,-7.62; 20 6.35,-7.62; 21 8.89,-7.62; 22 11.43,-7.62; 23 13.97,-7.62; 24 16.51,-7.62; 25 19.05,-7.62; 26 21.59,-7.62; 27 24.13,-7.62; 28 26.67,-7.62; 29 29.21,-7.62; 30 31.75,-7.62; 31 34.29,-7.62; 32 36.83,-7.62; 33 39.37,-7.62; 34 41.91,-7.62; 35 41.91,7.62; 36 39.37,7.62; 37 36.83,7.62; 38 34.29,7.62; 39 31.75,7.62; 40 29.21,7.62; 41 26.67,7.62; 42 24.13,7.62; 43 21.59,7.62; 44 19.05,7.62; 45 16.51,7.62; 46 13.97,7.62; 47 11.43,7.62; 48 8.89,7.62; 49 6.35,7.62; 50 3.81,7.62; 51 1.27,7.62; 52 -1.27,7.62; 53 -3.81,7.62; 54 -6.35,7.62; 55 -8.89,7.62; 56 -11.43,7.62; 57 -13.97,7.62; 58 -16.51,7.62; 59 -19.05,7.62; 60 -21.59,7.62; 61 -24.13,7.62; 62 -26.67,7.62; 63 -29.21,7.62; 64 -31.75,7.62; 65 -34.29,7.62; 66 -36.83,7.62; 67 -39.37,7.62; 68 -41.91,7.62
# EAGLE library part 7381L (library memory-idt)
MEMORY

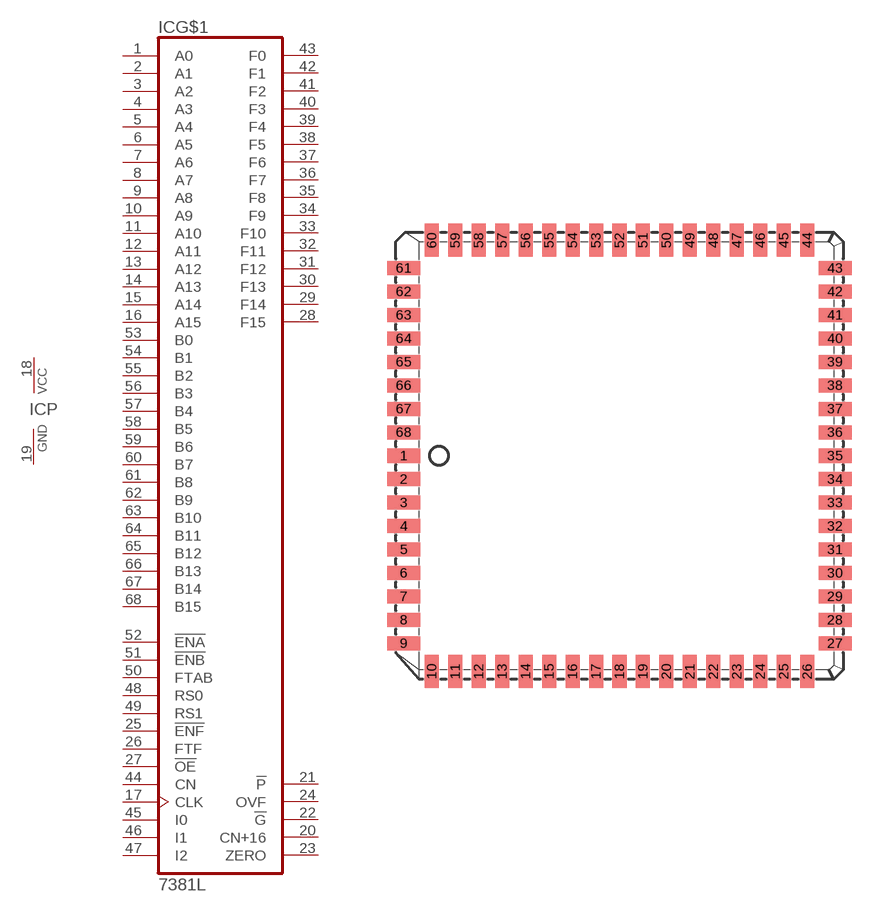
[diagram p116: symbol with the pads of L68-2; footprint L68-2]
Designator prefix IC; gates G$1=7381 P=VCCGND

## 7381L (OC_FARNELL: unknown; OC_NEWARK: unknown)  [L68-2]
1  G$1:A0  in
2  G$1:A1  in
3  G$1:A2  in
4  G$1:A3  in
5  G$1:A4  in
6  G$1:A5  in
7  G$1:A6  in
8  G$1:A7  in
9  G$1:A8  in
10  G$1:A9  in
11  G$1:A10  in
12  G$1:A11  in
13  G$1:A12  in
14  G$1:A13  in
15  G$1:A14  in
16  G$1:A15  in
17  G$1:CLK  in
18  P:VCC  pwr
19  P:GND  pwr
20  G$1:CN+16  out
21  G$1:!P  out
22  G$1:!G  out
23  G$1:ZERO  out
24  G$1:OVF  out
25  G$1:!ENF  in
26  G$1:FTF  in
27  G$1:!OE  in
28  G$1:F15  out
29  G$1:F14  out
30  G$1:F13  out
31  G$1:F12  out
32  G$1:F11  out
33  G$1:F10  out
34  G$1:F9  out
35  G$1:F8  out
36  G$1:F7  out
37  G$1:F6  out
38  G$1:F5  out
39  G$1:F4  out
40  G$1:F3  out
41  G$1:F2  out
42  G$1:F1  out
43  G$1:F0  out
44  G$1:CN  in
45  G$1:I0  in
46  G$1:I1  in
47  G$1:I2  in
48  G$1:RS0  in
49  G$1:RS1  in
50  G$1:FTAB  in
51  G$1:!ENB  in
52  G$1:!ENA  in
53  G$1:B0  in
54  G$1:B1  in
55  G$1:B2  in
56  G$1:B3  in
57  G$1:B4  in
58  G$1:B5  in
59  G$1:B6  in
60  G$1:B7  in
61  G$1:B8  in
62  G$1:B9  in
63  G$1:B10  in
64  G$1:B11  in
65  G$1:B12  in
66  G$1:B13  in
67  G$1:B14  in
68  G$1:B15  in

## Footprint L68-2 (pad centres in mm)
PLASTIC LEADED CHIP CARRIER square
smd 1.8 x 0.76: 1 -11.67,0; 2 -11.67,-1.27; 3 -11.67,-2.54; 4 -11.67,-3.81; 5 -11.67,-5.08; 6 -11.67,-6.35; 7 -11.67,-7.62; 8 -11.67,-8.89; 9 -11.67,-10.16; 27 11.67,-10.16; 28 11.67,-8.89; 29 11.67,-7.62; 30 11.67,-6.35; 31 11.67,-5.08; 32 11.67,-3.81; 33 11.67,-2.54; 34 11.67,-1.27; 35 11.67,0; 36 11.67,1.27; 37 11.67,2.54; 38 11.67,3.81; 39 11.67,5.08; 40 11.67,6.35; 41 11.67,7.62; 42 11.67,8.89; 43 11.67,10.16; 61 -11.67,10.16; 62 -11.67,8.89; 63 -11.67,7.62; 64 -11.67,6.35; 65 -11.67,5.08; 66 -11.67,3.81; 67 -11.67,2.54; 68 -11.67,1.27
smd 0.76 x 1.8: 10 -10.16,-11.67; 11 -8.89,-11.67; 12 -7.62,-11.67; 13 -6.35,-11.67; 14 -5.08,-11.67; 15 -3.81,-11.67; 16 -2.54,-11.67; 17 -1.27,-11.67; 18 0,-11.67; 19 1.27,-11.67; 20 2.54,-11.67; 21 3.81,-11.67; 22 5.08,-11.67; 23 6.35,-11.67; 24 7.62,-11.67; 25 8.89,-11.67; 26 10.16,-11.67; 44 10.16,11.67; 45 8.89,11.67; 46 7.62,11.67; 47 6.35,11.67; 48 5.08,11.67; 49 3.81,11.67; 50 2.54,11.67; 51 1.27,11.67; 52 0,11.67; 53 -1.27,11.67; 54 -2.54,11.67; 55 -3.81,11.67; 56 -5.08,11.67; 57 -6.35,11.67; 58 -7.62,11.67; 59 -8.89,11.67; 60 -10.16,11.67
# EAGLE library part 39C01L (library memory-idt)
MEMORY

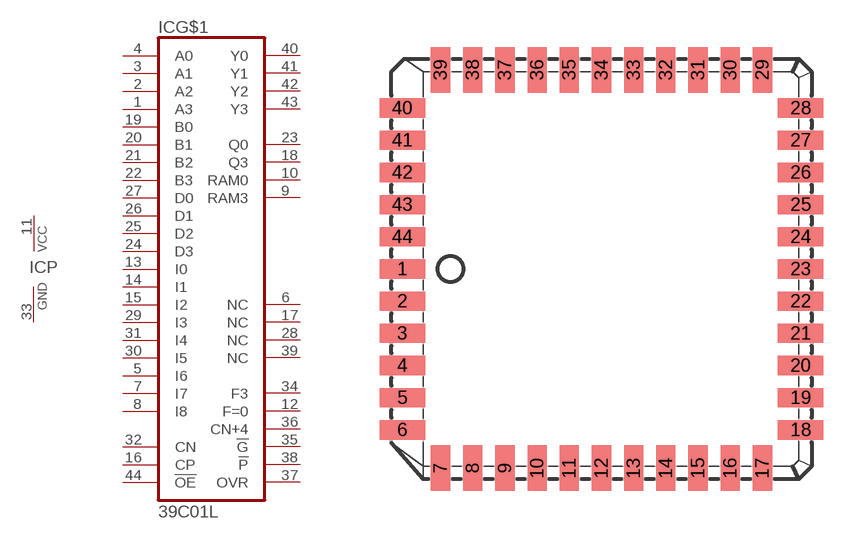
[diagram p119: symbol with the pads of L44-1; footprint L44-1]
Designator prefix IC; gates G$1=39C01L P=VCCGND

## 39C01L (OC_FARNELL: unknown; OC_NEWARK: unknown)  [L44-1]
1  G$1:A3  in
2  G$1:A2  in
3  G$1:A1  in
4  G$1:A0  in
5  G$1:I6  in
6  G$1:NC  nc
7  G$1:I7  in
8  G$1:I8  in
9  G$1:RAM3
10  G$1:RAM0
11  P:VCC  pwr
12  G$1:F=0  out
13  G$1:I0  in
14  G$1:I1  in
15  G$1:I2  in
16  G$1:CP  in
17  G$1:NC  nc
18  G$1:Q3
19  G$1:B0  in
20  G$1:B1  in
21  G$1:B2  in
22  G$1:B3  in
23  G$1:Q0
24  G$1:D3  in
25  G$1:D2  in
26  G$1:D1  in
27  G$1:D0  in
28  G$1:NC  nc
29  G$1:I3  in
30  G$1:I5  in
31  G$1:I4  in
32  G$1:CN  in
33  P:GND  pwr
34  G$1:F3  out
35  G$1:!G  out
36  G$1:CN+4  out
37  G$1:OVR  out
38  G$1:!P  out
39  G$1:NC  nc
40  G$1:Y0  out
41  G$1:Y1  out
42  G$1:Y2  out
43  G$1:Y3  out
44  G$1:!OE  in

## Footprint L44-1 (pad centres in mm)
PLASTIC LEADED CHIP CARRIER square
smd 1.8 x 0.76: 1 -7.86,0; 2 -7.86,-1.27; 3 -7.86,-2.54; 4 -7.86,-3.81; 5 -7.86,-5.08; 6 -7.86,-6.35; 18 7.86,-6.35; 19 7.86,-5.08; 20 7.86,-3.81; 21 7.86,-2.54; 22 7.86,-1.27; 23 7.86,0; 24 7.86,1.27; 25 7.86,2.54; 26 7.86,3.81; 27 7.86,5.08; 28 7.86,6.35; 40 -7.86,6.35; 41 -7.86,5.08; 42 -7.86,3.81; 43 -7.86,2.54; 44 -7.86,1.27
smd 0.76 x 1.8: 7 -6.35,-7.86; 8 -5.08,-7.86; 9 -3.81,-7.86; 10 -2.54,-7.86; 11 -1.27,-7.86; 12 0,-7.86; 13 1.27,-7.86; 14 2.54,-7.86; 15 3.81,-7.86; 16 5.08,-7.86; 17 6.35,-7.86; 29 6.35,7.86; 30 5.08,7.86; 31 3.81,7.86; 32 2.54,7.86; 33 1.27,7.86; 34 0,7.86; 35 -1.27,7.86; 36 -2.54,7.86; 37 -3.81,7.86; 38 -5.08,7.86; 39 -6.35,7.86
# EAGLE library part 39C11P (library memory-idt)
MEMORY

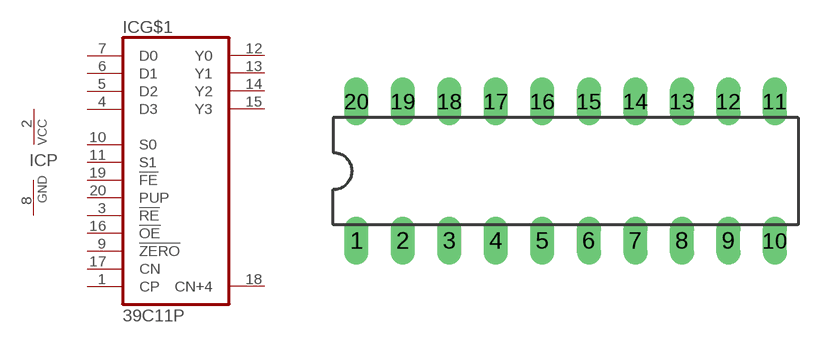
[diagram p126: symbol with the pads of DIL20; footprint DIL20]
Designator prefix IC; gates G$1=39C11 P=VCCGND

## 39C11P (OC_FARNELL: unknown; OC_NEWARK: unknown)  [DIL20]
1  G$1:CP  in
2  P:VCC  pwr
3  G$1:!RE  in
4  G$1:D3  in
5  G$1:D2  in
6  G$1:D1  in
7  G$1:D0  in
8  P:GND  pwr
9  G$1:!ZERO  in
10  G$1:S0  in
11  G$1:S1  in
12  G$1:Y0  out
13  G$1:Y1  out
14  G$1:Y2  out
15  G$1:Y3  out
16  G$1:!OE  in
17  G$1:CN  in
18  G$1:CN+4  out
19  G$1:!FE  in
20  G$1:PUP  in

## Footprint DIL20 (pad centres in mm)
Dual In Line Package
drill 0.813 long: 1 -11.43,-3.81; 2 -8.89,-3.81; 3 -6.35,-3.81; 4 -3.81,-3.81; 5 -1.27,-3.81; 6 1.27,-3.81; 7 3.81,-3.81; 8 6.35,-3.81; 9 8.89,-3.81; 10 11.43,-3.81; 11 11.43,3.81; 12 8.89,3.81; 13 6.35,3.81; 14 3.81,3.81; 15 1.27,3.81; 16 -1.27,3.81; 17 -3.81,3.81; 18 -6.35,3.81; 19 -8.89,3.81; 20 -11.43,3.81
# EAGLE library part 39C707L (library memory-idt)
MEMORY

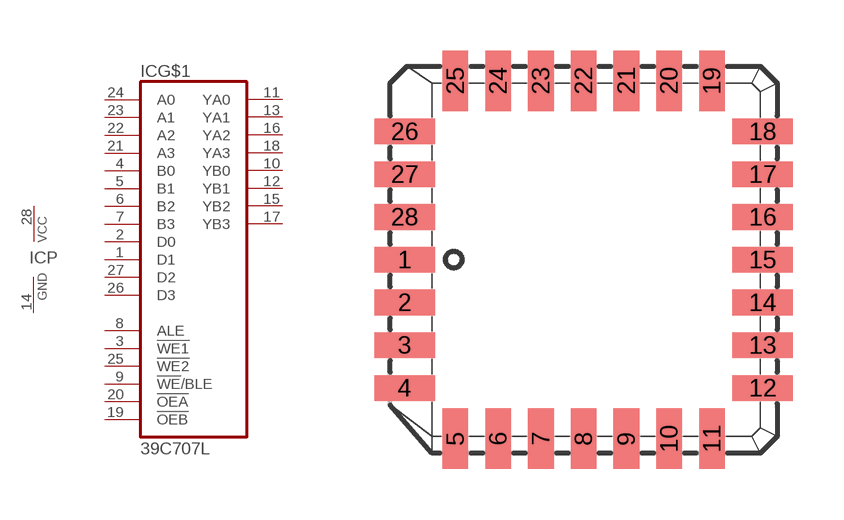
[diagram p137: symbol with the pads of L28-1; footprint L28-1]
Designator prefix IC; gates G$1=39C707 P=VCCGND

## 39C707L (OC_FARNELL: unknown; OC_NEWARK: unknown)  [L28-1]
1  G$1:D1  in
2  G$1:D0  in
3  G$1:!WE1  in
4  G$1:B0  in
5  G$1:B1  in
6  G$1:B2  in
7  G$1:B3  in
8  G$1:ALE  in
9  G$1:!WE!/BLE  in
10  G$1:YB0  out
11  G$1:YA0  out
12  G$1:YB1  out
13  G$1:YA1  out
14  P:GND  pwr
15  G$1:YB2  out
16  G$1:YA2  out
17  G$1:YB3  out
18  G$1:YA3  out
19  G$1:!OEB  in
20  G$1:!OEA  in
21  G$1:A3  in
22  G$1:A2  in
23  G$1:A1  in
24  G$1:A0  in
25  G$1:!WE2  in
26  G$1:D3  in
27  G$1:D2  in
28  P:VCC  pwr

## Footprint L28-1 (pad centres in mm)
PLASTIC LEADED CHIP CARRIER square
smd 1.8 x 0.76: 1 -5.32,0; 2 -5.32,-1.27; 3 -5.32,-2.54; 4 -5.32,-3.81; 12 5.32,-3.81; 13 5.32,-2.54; 14 5.32,-1.27; 15 5.32,0; 16 5.32,1.27; 17 5.32,2.54; 18 5.32,3.81; 26 -5.32,3.81; 27 -5.32,2.54; 28 -5.32,1.27
smd 0.76 x 1.8: 5 -3.81,-5.32; 6 -2.54,-5.32; 7 -1.27,-5.32; 8 0,-5.32; 9 1.27,-5.32; 10 2.54,-5.32; 11 3.81,-5.32; 19 3.81,5.32; 20 2.54,5.32; 21 1.27,5.32; 22 0,5.32; 23 -1.27,5.32; 24 -2.54,5.32; 25 -3.81,5.32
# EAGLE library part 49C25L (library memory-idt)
MEMORY

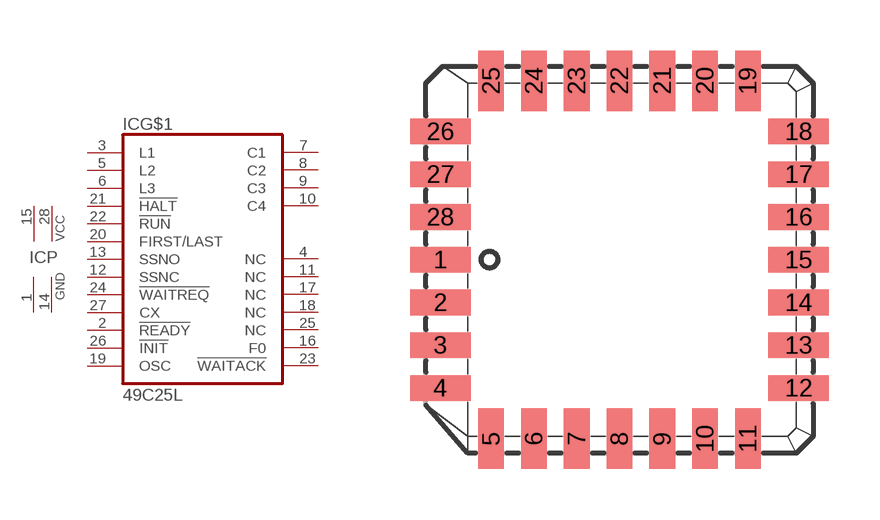
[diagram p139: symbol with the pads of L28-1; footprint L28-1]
Designator prefix IC; gates G$1=49C25L P=2VCC2GND

## 49C25L (OC_FARNELL: unknown; OC_NEWARK: unknown)  [L28-1]
1  P:GND  pwr
2  G$1:!READY  in
3  G$1:L1  in
4  G$1:NC  nc
5  G$1:L2  in
6  G$1:L3  in
7  G$1:C1  out
8  G$1:C2  out
9  G$1:C3  out
10  G$1:C4  out
11  G$1:NC  nc
12  G$1:SSNC  in
13  G$1:SSNO  in
14  P:GND  pwr
15  P:VCC  pwr
16  G$1:F0  out
17  G$1:NC  nc
18  G$1:NC  nc
19  G$1:OSC  in
20  G$1:FIRST/LAST  in
21  G$1:!HALT  in
22  G$1:!RUN  in
23  G$1:!WAITACK  out
24  G$1:!WAITREQ  in
25  G$1:NC  nc
26  G$1:!INIT  in
27  G$1:CX  in
28  P:VCC  pwr

## Footprint L28-1 (pad centres in mm)
PLASTIC LEADED CHIP CARRIER square
smd 1.8 x 0.76: 1 -5.32,0; 2 -5.32,-1.27; 3 -5.32,-2.54; 4 -5.32,-3.81; 12 5.32,-3.81; 13 5.32,-2.54; 14 5.32,-1.27; 15 5.32,0; 16 5.32,1.27; 17 5.32,2.54; 18 5.32,3.81; 26 -5.32,3.81; 27 -5.32,2.54; 28 -5.32,1.27
smd 0.76 x 1.8: 5 -3.81,-5.32; 6 -2.54,-5.32; 7 -1.27,-5.32; 8 0,-5.32; 9 1.27,-5.32; 10 2.54,-5.32; 11 3.81,-5.32; 19 3.81,5.32; 20 2.54,5.32; 21 1.27,5.32; 22 0,5.32; 23 -1.27,5.32; 24 -2.54,5.32; 25 -3.81,5.32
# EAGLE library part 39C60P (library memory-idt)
MEMORY

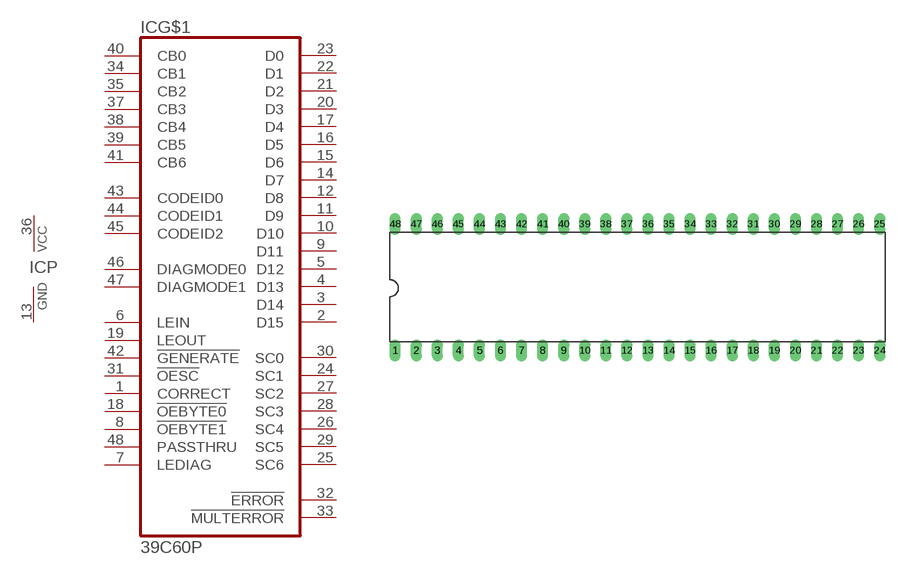
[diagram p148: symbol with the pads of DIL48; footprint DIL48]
Designator prefix IC; gates G$1=39C60-48 P=VCCGND

## 39C60P (OC_FARNELL: unknown; OC_NEWARK: unknown)  [DIL48]
1  G$1:CORRECT  in
2  G$1:D15
3  G$1:D14
4  G$1:D13
5  G$1:D12
6  G$1:LEIN  in
7  G$1:LEDIAG  in
8  G$1:!OEBYTE1  in
9  G$1:D11
10  G$1:D10
11  G$1:D9
12  G$1:D8
13  P:GND  pwr
14  G$1:D7
15  G$1:D6
16  G$1:D5
17  G$1:D4
18  G$1:!OEBYTE0  in
19  G$1:LEOUT  in
20  G$1:D3
21  G$1:D2
22  G$1:D1
23  G$1:D0
24  G$1:SC1  out
25  G$1:SC6  out
26  G$1:SC4  out
27  G$1:SC2  out
28  G$1:SC3  out
29  G$1:SC5  out
30  G$1:SC0  out
31  G$1:!OESC  in
32  G$1:!ERROR  out
33  G$1:!MULTERROR  out
34  G$1:CB1  in
35  G$1:CB2  in
36  P:VCC  pwr
37  G$1:CB3  in
38  G$1:CB4  in
39  G$1:CB5  in
40  G$1:CB0  in
41  G$1:CB6  in
42  G$1:!GENERATE  in
43  G$1:CODEID0  in
44  G$1:CODEID1  in
45  G$1:CODEID2  in
46  G$1:DIAGMODE0  in
47  G$1:DIAGMODE1  in
48  G$1:PASSTHRU  in

## Footprint DIL48 (pad centres in mm)
Dual In Line Package
drill 0.813 long: 1 -29.21,-7.62; 2 -26.67,-7.62; 3 -24.13,-7.62; 4 -21.59,-7.62; 5 -19.05,-7.62; 6 -16.51,-7.62; 7 -13.97,-7.62; 8 -11.43,-7.62; 9 -8.89,-7.62; 10 -6.35,-7.62; 11 -3.81,-7.62; 12 -1.27,-7.62; 13 1.27,-7.62; 14 3.81,-7.62; 15 6.35,-7.62; 16 8.89,-7.62; 17 11.43,-7.62; 18 13.97,-7.62; 19 16.51,-7.62; 20 19.05,-7.62; 21 21.59,-7.62; 22 24.13,-7.62; 23 26.67,-7.62; 24 29.21,-7.62; 25 29.21,7.62; 26 26.67,7.62; 27 24.13,7.62; 28 21.59,7.62; 29 19.05,7.62; 30 16.51,7.62; 31 13.97,7.62; 32 11.43,7.62; 33 8.89,7.62; 34 6.35,7.62; 35 3.81,7.62; 36 1.27,7.62; 37 -1.27,7.62; 38 -3.81,7.62; 39 -6.35,7.62; 40 -8.89,7.62; 41 -11.43,7.62; 42 -13.97,7.62; 43 -16.51,7.62; 44 -19.05,7.62; 45 -21.59,7.62; 46 -24.13,7.62; 47 -26.67,7.62; 48 -29.21,7.62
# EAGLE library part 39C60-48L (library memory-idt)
MEMORY

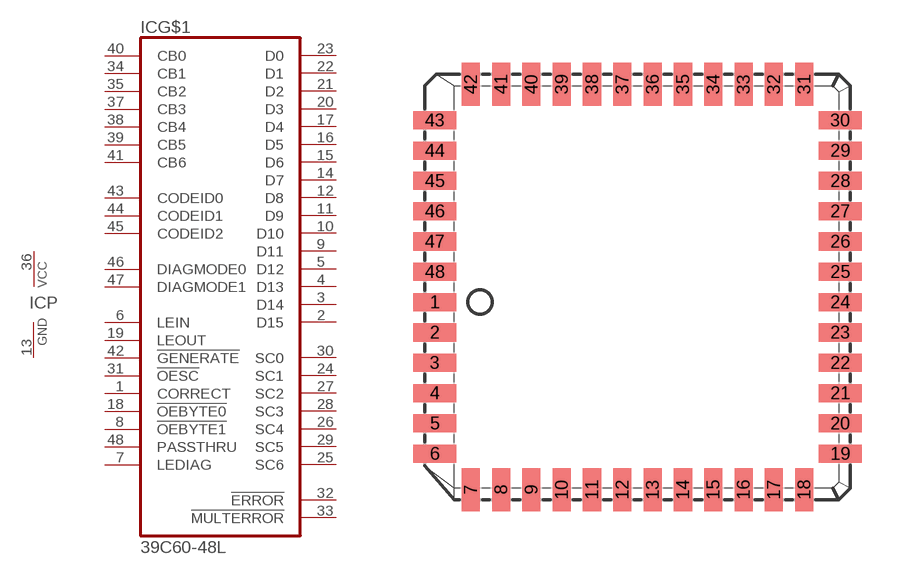
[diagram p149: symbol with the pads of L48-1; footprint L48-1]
Designator prefix IC; gates G$1=39C60-48 P=VCCGND

## 39C60-48L (OC_FARNELL: unknown; OC_NEWARK: unknown)  [L48-1]
1  G$1:CORRECT  in
2  G$1:D15
3  G$1:D14
4  G$1:D13
5  G$1:D12
6  G$1:LEIN  in
7  G$1:LEDIAG  in
8  G$1:!OEBYTE1  in
9  G$1:D11
10  G$1:D10
11  G$1:D9
12  G$1:D8
13  P:GND  pwr
14  G$1:D7
15  G$1:D6
16  G$1:D5
17  G$1:D4
18  G$1:!OEBYTE0  in
19  G$1:LEOUT  in
20  G$1:D3
21  G$1:D2
22  G$1:D1
23  G$1:D0
24  G$1:SC1  out
25  G$1:SC6  out
26  G$1:SC4  out
27  G$1:SC2  out
28  G$1:SC3  out
29  G$1:SC5  out
30  G$1:SC0  out
31  G$1:!OESC  in
32  G$1:!ERROR  out
33  G$1:!MULTERROR  out
34  G$1:CB1  in
35  G$1:CB2  in
36  P:VCC  pwr
37  G$1:CB3  in
38  G$1:CB4  in
39  G$1:CB5  in
40  G$1:CB0  in
41  G$1:CB6  in
42  G$1:!GENERATE  in
43  G$1:CODEID0  in
44  G$1:CODEID1  in
45  G$1:CODEID2  in
46  G$1:DIAGMODE0  in
47  G$1:DIAGMODE1  in
48  G$1:PASSTHRU  in

## Footprint L48-1 (pad centres in mm)
PLASTIC LEADED CHIP CARRIER square
smd 1.8 x 0.76: 1 -7.86,0; 2 -7.86,-1.27; 3 -7.86,-2.54; 4 -7.86,-3.81; 5 -7.86,-5.08; 6 -7.86,-6.35; 19 9.13,-6.35; 20 9.13,-5.08; 21 9.13,-3.81; 22 9.13,-2.54; 23 9.13,-1.27; 24 9.13,0; 25 9.13,1.27; 26 9.13,2.54; 27 9.13,3.81; 28 9.13,5.08; 29 9.13,6.35; 30 9.13,7.62; 43 -7.86,7.62; 44 -7.86,6.35; 45 -7.86,5.08; 46 -7.86,3.81; 47 -7.86,2.54; 48 -7.86,1.27
smd 0.76 x 1.8: 7 -6.35,-7.86; 8 -5.08,-7.86; 9 -3.81,-7.86; 10 -2.54,-7.86; 11 -1.27,-7.86; 12 0,-7.86; 13 1.27,-7.86; 14 2.54,-7.86; 15 3.81,-7.86; 16 5.08,-7.86; 17 6.35,-7.86; 18 7.62,-7.86; 31 7.62,9.13; 32 6.35,9.13; 33 5.08,9.13; 34 3.81,9.13; 35 2.54,9.13; 36 1.27,9.13; 37 0,9.13; 38 -1.27,9.13; 39 -2.54,9.13; 40 -3.81,9.13; 41 -5.08,9.13; 42 -6.35,9.13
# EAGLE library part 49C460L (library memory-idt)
MEMORY

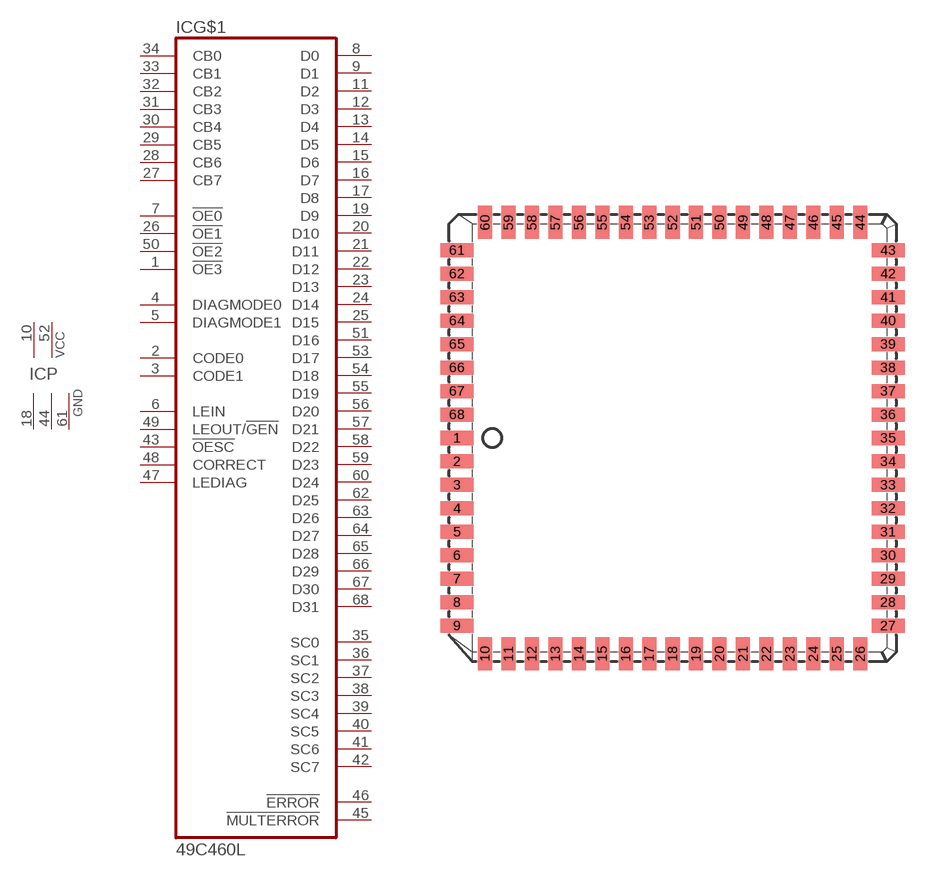
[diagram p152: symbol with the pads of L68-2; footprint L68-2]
Designator prefix IC; gates G$1=49C460 P=2VCC3GND

## 49C460L (OC_FARNELL: unknown; OC_NEWARK: unknown)  [L68-2]
1  G$1:!OE3  in
2  G$1:CODE0  in
3  G$1:CODE1  in
4  G$1:DIAGMODE0  in
5  G$1:DIAGMODE1  in
6  G$1:LEIN  in
7  G$1:!OE0  in
8  G$1:D0
9  G$1:D1
10  P:VCC  pwr
11  G$1:D2
12  G$1:D3
13  G$1:D4
14  G$1:D5
15  G$1:D6
16  G$1:D7
17  G$1:D8
18  P:GND  pwr
19  G$1:D9
20  G$1:D10
21  G$1:D11
22  G$1:D12
23  G$1:D13
24  G$1:D14
25  G$1:D15
26  G$1:!OE1  in
27  G$1:CB7  in
28  G$1:CB6  in
29  G$1:CB5  in
30  G$1:CB4  in
31  G$1:CB3  in
32  G$1:CB2  in
33  G$1:CB1  in
34  G$1:CB0  in
35  G$1:SC0  out
36  G$1:SC1  out
37  G$1:SC2  out
38  G$1:SC3  out
39  G$1:SC4  out
40  G$1:SC5  out
41  G$1:SC6  out
42  G$1:SC7  out
43  G$1:!OESC  in
44  P:GND  pwr
45  G$1:!MULTERROR  out
46  G$1:!ERROR  out
47  G$1:LEDIAG  in
48  G$1:CORRECT  in
49  G$1:LEOUT/!GEN  in
50  G$1:!OE2  in
51  G$1:D16
52  P:VCC  pwr
53  G$1:D17
54  G$1:D18
55  G$1:D19
56  G$1:D20
57  G$1:D21
58  G$1:D22
59  G$1:D23
60  G$1:D24
61  P:GND  pwr
62  G$1:D25
63  G$1:D26
64  G$1:D27
65  G$1:D28
66  G$1:D29
67  G$1:D30
68  G$1:D31

## Footprint L68-2 (pad centres in mm)
PLASTIC LEADED CHIP CARRIER square
smd 1.8 x 0.76: 1 -11.67,0; 2 -11.67,-1.27; 3 -11.67,-2.54; 4 -11.67,-3.81; 5 -11.67,-5.08; 6 -11.67,-6.35; 7 -11.67,-7.62; 8 -11.67,-8.89; 9 -11.67,-10.16; 27 11.67,-10.16; 28 11.67,-8.89; 29 11.67,-7.62; 30 11.67,-6.35; 31 11.67,-5.08; 32 11.67,-3.81; 33 11.67,-2.54; 34 11.67,-1.27; 35 11.67,0; 36 11.67,1.27; 37 11.67,2.54; 38 11.67,3.81; 39 11.67,5.08; 40 11.67,6.35; 41 11.67,7.62; 42 11.67,8.89; 43 11.67,10.16; 61 -11.67,10.16; 62 -11.67,8.89; 63 -11.67,7.62; 64 -11.67,6.35; 65 -11.67,5.08; 66 -11.67,3.81; 67 -11.67,2.54; 68 -11.67,1.27
smd 0.76 x 1.8: 10 -10.16,-11.67; 11 -8.89,-11.67; 12 -7.62,-11.67; 13 -6.35,-11.67; 14 -5.08,-11.67; 15 -3.81,-11.67; 16 -2.54,-11.67; 17 -1.27,-11.67; 18 0,-11.67; 19 1.27,-11.67; 20 2.54,-11.67; 21 3.81,-11.67; 22 5.08,-11.67; 23 6.35,-11.67; 24 7.62,-11.67; 25 8.89,-11.67; 26 10.16,-11.67; 44 10.16,11.67; 45 8.89,11.67; 46 7.62,11.67; 47 6.35,11.67; 48 5.08,11.67; 49 3.81,11.67; 50 2.54,11.67; 51 1.27,11.67; 52 0,11.67; 53 -1.27,11.67; 54 -2.54,11.67; 55 -3.81,11.67; 56 -5.08,11.67; 57 -6.35,11.67; 58 -7.62,11.67; 59 -8.89,11.67; 60 -10.16,11.67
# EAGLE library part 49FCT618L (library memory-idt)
MEMORY

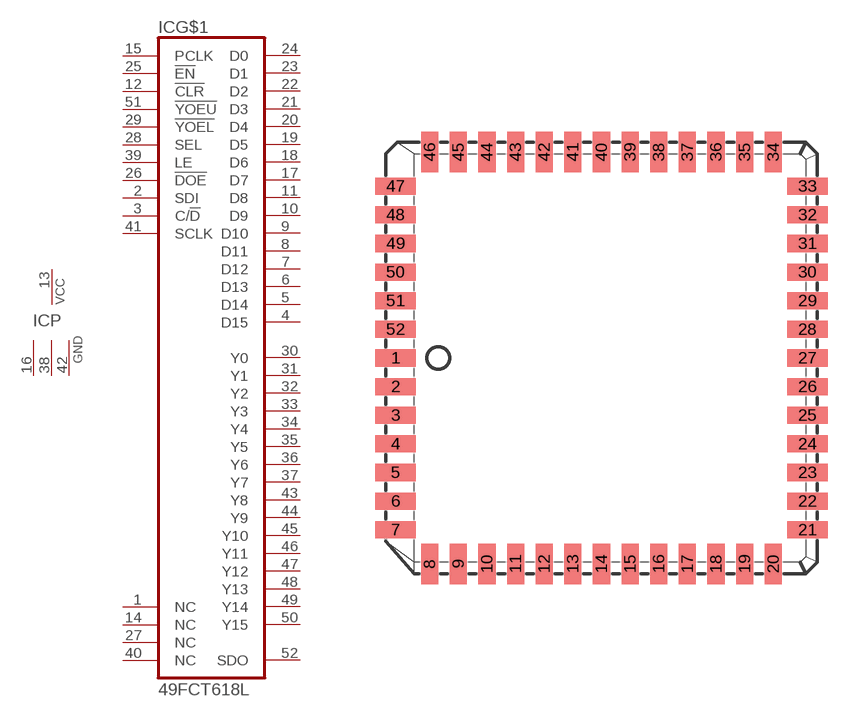
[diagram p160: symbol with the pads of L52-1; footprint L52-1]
Designator prefix IC; gates G$1=618L P=1VCC3GND

## 49FCT618L (OC_FARNELL: unknown; OC_NEWARK: unknown)  [L52-1]
1  G$1:NC  nc
2  G$1:SDI  in
3  G$1:C/!D  in
4  G$1:D15
5  G$1:D14
6  G$1:D13
7  G$1:D12
8  G$1:D11
9  G$1:D10
10  G$1:D9
11  G$1:D8
12  G$1:!CLR  in
13  P:VCC  pwr
14  G$1:NC  nc
15  G$1:PCLK  in
16  P:GND  pwr
17  G$1:D7
18  G$1:D6
19  G$1:D5
20  G$1:D4
21  G$1:D3
22  G$1:D2
23  G$1:D1
24  G$1:D0
25  G$1:!EN  in
26  G$1:!DOE  in
27  G$1:NC  nc
28  G$1:SEL  in
29  G$1:!YOEL  in
30  G$1:Y0
31  G$1:Y1
32  G$1:Y2
33  G$1:Y3
34  G$1:Y4
35  G$1:Y5
36  G$1:Y6
37  G$1:Y7
38  P:GND  pwr
39  G$1:LE  in
40  G$1:NC  nc
41  G$1:SCLK  in
42  P:GND  pwr
43  G$1:Y8
44  G$1:Y9
45  G$1:Y10
46  G$1:Y11
47  G$1:Y12
48  G$1:Y13
49  G$1:Y14
50  G$1:Y15
51  G$1:!YOEU  in
52  G$1:SDO  out

## Footprint L52-1 (pad centres in mm)
PLASTIC LEADED CHIP CARRIER square
smd 1.8 x 0.76: 1 -9.13,0; 2 -9.13,-1.27; 3 -9.13,-2.54; 4 -9.13,-3.81; 5 -9.13,-5.08; 6 -9.13,-6.35; 7 -9.13,-7.62; 21 9.13,-7.62; 22 9.13,-6.35; 23 9.13,-5.08; 24 9.13,-3.81; 25 9.13,-2.54; 26 9.13,-1.27; 27 9.13,0; 28 9.13,1.27; 29 9.13,2.54; 30 9.13,3.81; 31 9.13,5.08; 32 9.13,6.35; 33 9.13,7.62; 47 -9.13,7.62; 48 -9.13,6.35; 49 -9.13,5.08; 50 -9.13,3.81; 51 -9.13,2.54; 52 -9.13,1.27
smd 0.76 x 1.8: 8 -7.62,-9.13; 9 -6.35,-9.13; 10 -5.08,-9.13; 11 -3.81,-9.13; 12 -2.54,-9.13; 13 -1.27,-9.13; 14 0,-9.13; 15 1.27,-9.13; 16 2.54,-9.13; 17 3.81,-9.13; 18 5.08,-9.13; 19 6.35,-9.13; 20 7.62,-9.13; 34 7.62,9.13; 35 6.35,9.13; 36 5.08,9.13; 37 3.81,9.13; 38 2.54,9.13; 39 1.27,9.13; 40 0,9.13; 41 -1.27,9.13; 42 -2.54,9.13; 43 -3.81,9.13; 44 -5.08,9.13; 45 -6.35,9.13; 46 -7.62,9.13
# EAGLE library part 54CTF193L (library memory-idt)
MEMORY

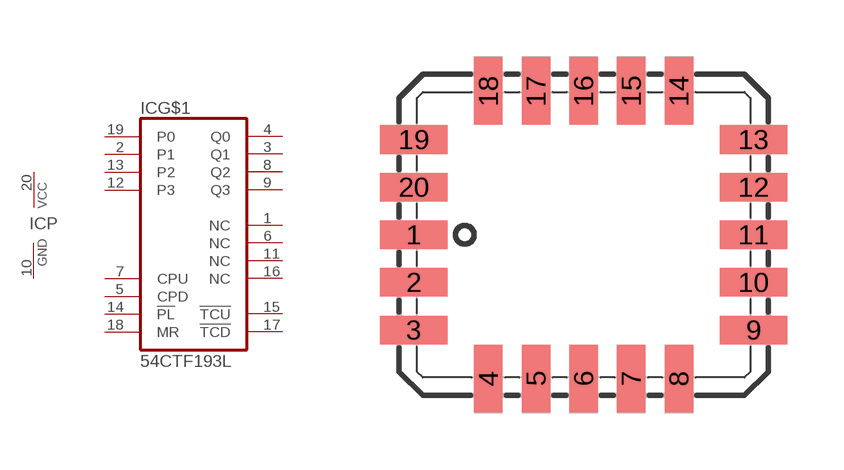
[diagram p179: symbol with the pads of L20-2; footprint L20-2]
Designator prefix IC; gates G$1=54193L P=VCCGND

## 54CTF193L (OC_FARNELL: unknown; OC_NEWARK: unknown)  [L20-2]
1  G$1:NC  nc
2  G$1:P1  in
3  G$1:Q1  out
4  G$1:Q0  out
5  G$1:CPD  in
6  G$1:NC  nc
7  G$1:CPU  in
8  G$1:Q2  out
9  G$1:Q3  out
10  P:GND  pwr
11  G$1:NC  nc
12  G$1:P3  in
13  G$1:P2  in
14  G$1:!PL  in
15  G$1:!TCU  out
16  G$1:NC  nc
17  G$1:!TCD  out
18  G$1:MR  in
19  G$1:P0  in
20  P:VCC  pwr

## Footprint L20-2 (pad centres in mm)
PLASTIC LEADED CHIP CARRIER rectangle
smd 1.8 x 0.76: 1 -4.53,-0.635; 2 -4.53,-1.905; 3 -4.53,-3.175; 9 4.53,-3.175; 10 4.53,-1.905; 11 4.53,-0.635; 12 4.53,0.635; 13 4.53,1.905; 19 -4.53,1.905; 20 -4.53,0.635
smd 0.76 x 1.8: 4 -2.54,-4.47; 5 -1.27,-4.47; 6 0,-4.47; 7 1.27,-4.47; 8 2.54,-4.47; 14 2.54,3.2; 15 1.27,3.2; 16 0,3.2; 17 -1.27,3.2; 18 -2.54,3.2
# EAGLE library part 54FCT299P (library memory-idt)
MEMORY

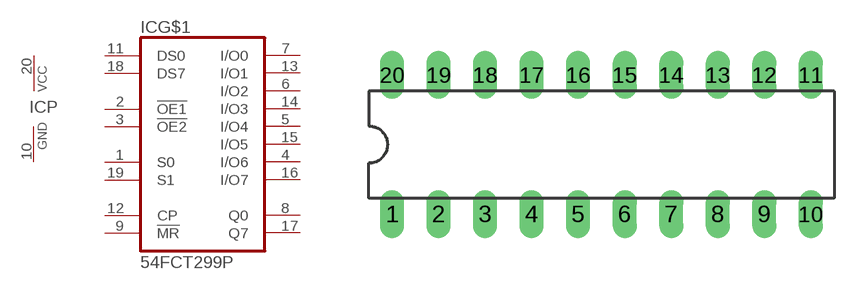
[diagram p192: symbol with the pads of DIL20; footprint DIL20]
Designator prefix IC; gates G$1=299 P=VCCGND

## 54FCT299P (OC_FARNELL: unknown; OC_NEWARK: unknown)  [DIL20]
1  G$1:S0
2  G$1:!OE1
3  G$1:!OE2
4  G$1:I/O6
5  G$1:I/O4
6  G$1:I/O2
7  G$1:I/O0
8  G$1:Q0  out
9  G$1:!MR
10  P:GND  pwr
11  G$1:DS0
12  G$1:CP
13  G$1:I/O1
14  G$1:I/O3
15  G$1:I/O5
16  G$1:I/O7
17  G$1:Q7  out
18  G$1:DS7
19  G$1:S1
20  P:VCC  pwr

## Footprint DIL20 (pad centres in mm)
Dual In Line Package
drill 0.813 long: 1 -11.43,-3.81; 2 -8.89,-3.81; 3 -6.35,-3.81; 4 -3.81,-3.81; 5 -1.27,-3.81; 6 1.27,-3.81; 7 3.81,-3.81; 8 6.35,-3.81; 9 8.89,-3.81; 10 11.43,-3.81; 11 11.43,3.81; 12 8.89,3.81; 13 6.35,3.81; 14 3.81,3.81; 15 1.27,3.81; 16 -1.27,3.81; 17 -3.81,3.81; 18 -6.35,3.81; 19 -8.89,3.81; 20 -11.43,3.81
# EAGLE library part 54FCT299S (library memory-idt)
MEMORY

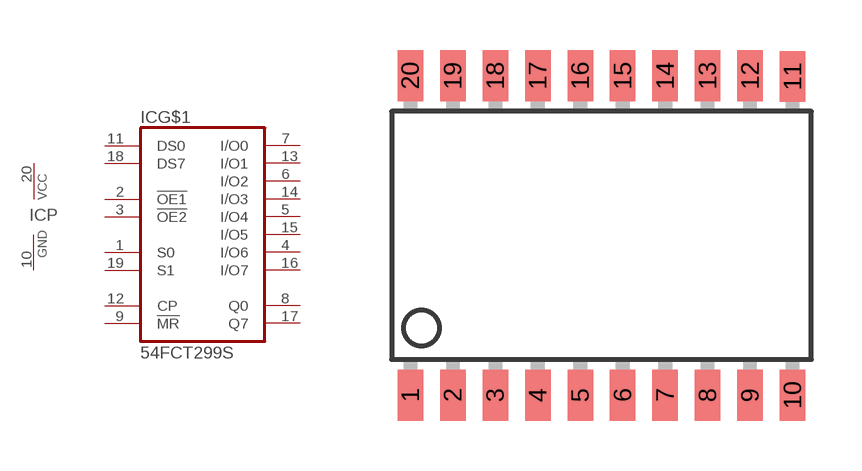
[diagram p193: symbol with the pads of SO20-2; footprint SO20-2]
Designator prefix IC; gates G$1=299 P=VCCGND

## 54FCT299S (OC_FARNELL: unknown; OC_NEWARK: unknown)  [SO20-2]
1  G$1:S0
2  G$1:!OE1
3  G$1:!OE2
4  G$1:I/O6
5  G$1:I/O4
6  G$1:I/O2
7  G$1:I/O0
8  G$1:Q0  out
9  G$1:!MR
10  P:GND  pwr
11  G$1:DS0
12  G$1:CP
13  G$1:I/O1
14  G$1:I/O3
15  G$1:I/O5
16  G$1:I/O7
17  G$1:Q7  out
18  G$1:DS7
19  G$1:S1
20  P:VCC  pwr

## Footprint SO20-2 (pad centres in mm)
Small Outline Package
smd 0.762 x 1.524: 1 -5.715,-4.775; 2 -4.445,-4.775; 3 -3.175,-4.775; 4 -1.905,-4.775; 5 -0.635,-4.775; 6 0.635,-4.775; 7 1.905,-4.775; 8 3.175,-4.775; 9 4.445,-4.775; 10 5.715,-4.775; 11 5.715,4.75; 12 4.445,4.775; 13 3.175,4.775; 14 1.905,4.775; 15 0.635,4.775; 16 -0.635,4.775; 17 -1.905,4.775; 18 -3.175,4.775; 19 -4.445,4.775; 20 -5.715,4.775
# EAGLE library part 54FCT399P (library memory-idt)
MEMORY

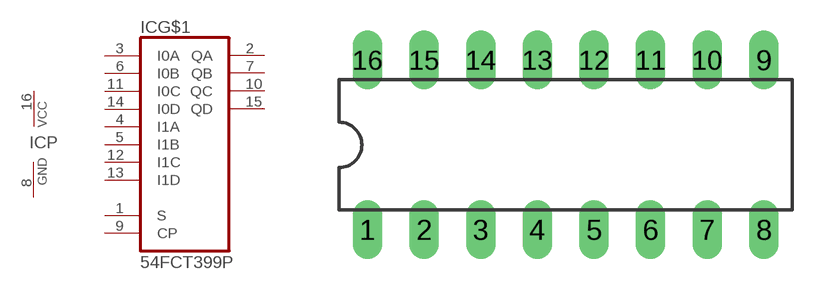
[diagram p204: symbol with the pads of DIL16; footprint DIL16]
Designator prefix IC; gates G$1=399 P=VCCGND

## 54FCT399P (OC_FARNELL: unknown; OC_NEWARK: unknown)  [DIL16]
1  G$1:S  in
2  G$1:QA  out
3  G$1:I0A  in
4  G$1:I1A  in
5  G$1:I1B  in
6  G$1:I0B  in
7  G$1:QB  out
8  P:GND  pwr
9  G$1:CP  in
10  G$1:QC  out
11  G$1:I0C  in
12  G$1:I1C  in
13  G$1:I1D  in
14  G$1:I0D  in
15  G$1:QD  out
16  P:VCC  pwr

## Footprint DIL16 (pad centres in mm)
Dual In Line Package
drill 0.813 long: 1 -8.89,-3.81; 2 -6.35,-3.81; 3 -3.81,-3.81; 4 -1.27,-3.81; 5 1.27,-3.81; 6 3.81,-3.81; 7 6.35,-3.81; 8 8.89,-3.81; 9 8.89,3.81; 10 6.35,3.81; 11 3.81,3.81; 12 1.27,3.81; 13 -1.27,3.81; 14 -3.81,3.81; 15 -6.35,3.81; 16 -8.89,3.81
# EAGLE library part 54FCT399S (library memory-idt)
MEMORY

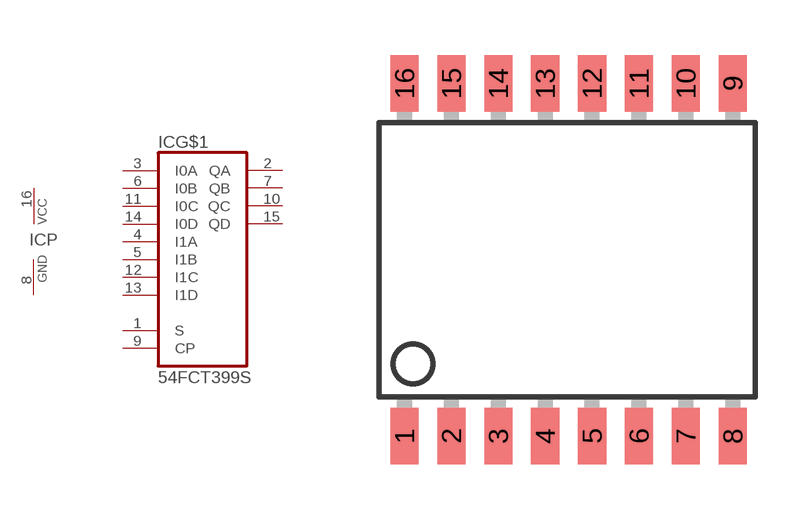
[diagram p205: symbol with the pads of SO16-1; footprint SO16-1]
Designator prefix IC; gates G$1=399 P=VCCGND

## 54FCT399S (OC_FARNELL: unknown; OC_NEWARK: unknown)  [SO16-1]
1  G$1:S  in
2  G$1:QA  out
3  G$1:I0A  in
4  G$1:I1A  in
5  G$1:I1B  in
6  G$1:I0B  in
7  G$1:QB  out
8  P:GND  pwr
9  G$1:CP  in
10  G$1:QC  out
11  G$1:I0C  in
12  G$1:I1C  in
13  G$1:I1D  in
14  G$1:I0D  in
15  G$1:QD  out
16  P:VCC  pwr

## Footprint SO16-1 (pad centres in mm)
Small Outline Package
smd 0.762 x 1.524: 1 -4.445,-4.775; 2 -3.175,-4.775; 3 -1.905,-4.775; 4 -0.635,-4.775; 5 0.635,-4.775; 6 1.905,-4.775; 7 3.175,-4.775; 8 4.445,-4.775; 9 4.445,4.775; 10 3.175,4.775; 11 1.905,4.775; 12 0.635,4.775; 13 -0.635,4.775; 14 -1.905,4.775; 15 -3.175,4.775; 16 -4.445,4.775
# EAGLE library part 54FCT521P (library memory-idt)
MEMORY

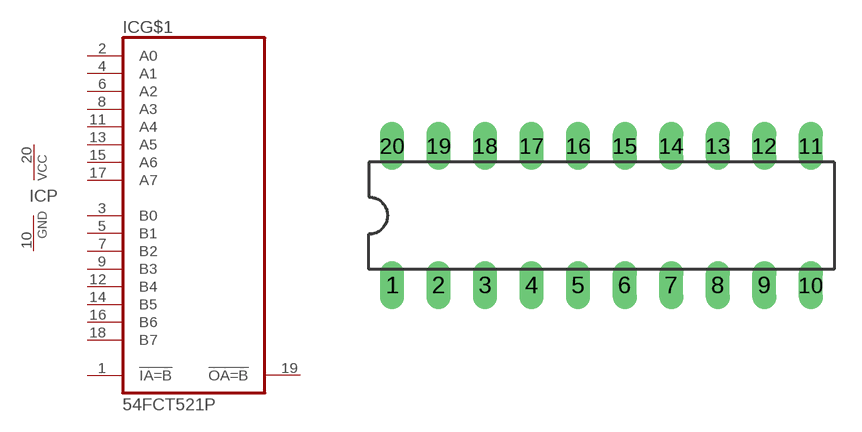
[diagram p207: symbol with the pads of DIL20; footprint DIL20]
Designator prefix IC; gates G$1=521 P=VCCGND

## 54FCT521P (OC_FARNELL: unknown; OC_NEWARK: unknown)  [DIL20]
1  G$1:!IA=B  in
2  G$1:A0  in
3  G$1:B0  in
4  G$1:A1  in
5  G$1:B1  in
6  G$1:A2  in
7  G$1:B2  in
8  G$1:A3  in
9  G$1:B3  in
10  P:GND  pwr
11  G$1:A4  in
12  G$1:B4  in
13  G$1:A5  in
14  G$1:B5  in
15  G$1:A6  in
16  G$1:B6  in
17  G$1:A7  in
18  G$1:B7  in
19  G$1:!OA=B  out
20  P:VCC  pwr

## Footprint DIL20 (pad centres in mm)
Dual In Line Package
drill 0.813 long: 1 -11.43,-3.81; 2 -8.89,-3.81; 3 -6.35,-3.81; 4 -3.81,-3.81; 5 -1.27,-3.81; 6 1.27,-3.81; 7 3.81,-3.81; 8 6.35,-3.81; 9 8.89,-3.81; 10 11.43,-3.81; 11 11.43,3.81; 12 8.89,3.81; 13 6.35,3.81; 14 3.81,3.81; 15 1.27,3.81; 16 -1.27,3.81; 17 -3.81,3.81; 18 -6.35,3.81; 19 -8.89,3.81; 20 -11.43,3.81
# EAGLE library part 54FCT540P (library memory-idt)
MEMORY

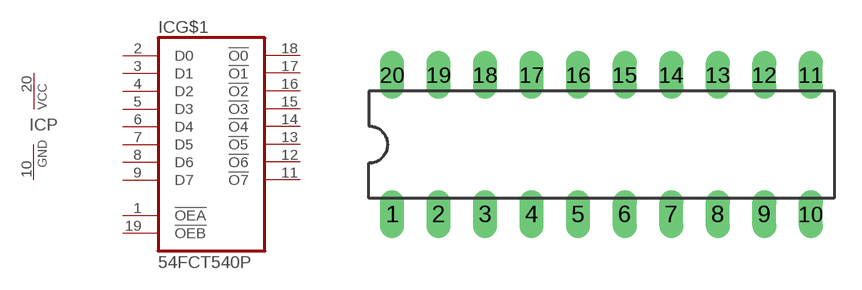
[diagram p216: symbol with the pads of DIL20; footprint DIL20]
Designator prefix IC; gates G$1=540 P=VCCGND

## 54FCT540P (OC_FARNELL: unknown; OC_NEWARK: unknown)  [DIL20]
1  G$1:!OEA  in
2  G$1:D0  in
3  G$1:D1  in
4  G$1:D2  in
5  G$1:D3  in
6  G$1:D4  in
7  G$1:D5  in
8  G$1:D6  in
9  G$1:D7  in
10  P:GND  pwr
11  G$1:!O7  out
12  G$1:!O6  out
13  G$1:!O5  out
14  G$1:!O4  out
15  G$1:!O3  out
16  G$1:!O2  out
17  G$1:!O1  out
18  G$1:!O0  out
19  G$1:!OEB  in
20  P:VCC  pwr

## Footprint DIL20 (pad centres in mm)
Dual In Line Package
drill 0.813 long: 1 -11.43,-3.81; 2 -8.89,-3.81; 3 -6.35,-3.81; 4 -3.81,-3.81; 5 -1.27,-3.81; 6 1.27,-3.81; 7 3.81,-3.81; 8 6.35,-3.81; 9 8.89,-3.81; 10 11.43,-3.81; 11 11.43,3.81; 12 8.89,3.81; 13 6.35,3.81; 14 3.81,3.81; 15 1.27,3.81; 16 -1.27,3.81; 17 -3.81,3.81; 18 -6.35,3.81; 19 -8.89,3.81; 20 -11.43,3.81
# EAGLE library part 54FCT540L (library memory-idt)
MEMORY

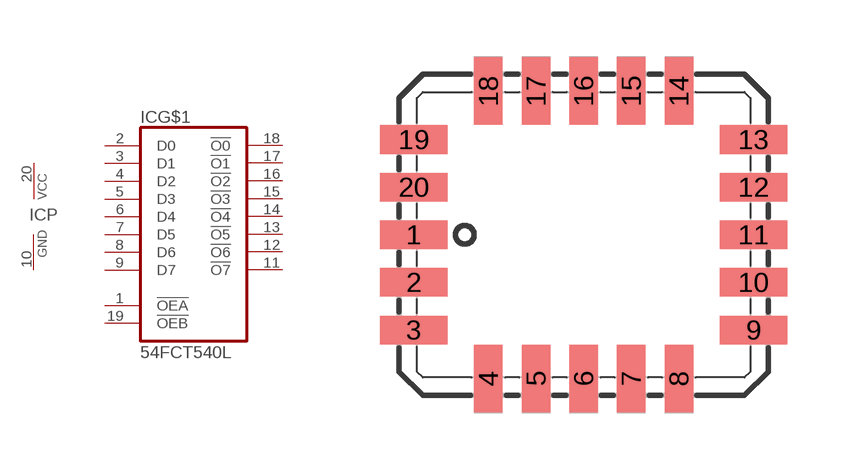
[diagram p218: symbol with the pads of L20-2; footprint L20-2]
Designator prefix IC; gates G$1=540 P=VCCGND

## 54FCT540L (OC_FARNELL: unknown; OC_NEWARK: unknown)  [L20-2]
1  G$1:!OEA  in
2  G$1:D0  in
3  G$1:D1  in
4  G$1:D2  in
5  G$1:D3  in
6  G$1:D4  in
7  G$1:D5  in
8  G$1:D6  in
9  G$1:D7  in
10  P:GND  pwr
11  G$1:!O7  out
12  G$1:!O6  out
13  G$1:!O5  out
14  G$1:!O4  out
15  G$1:!O3  out
16  G$1:!O2  out
17  G$1:!O1  out
18  G$1:!O0  out
19  G$1:!OEB  in
20  P:VCC  pwr

## Footprint L20-2 (pad centres in mm)
PLASTIC LEADED CHIP CARRIER rectangle
smd 1.8 x 0.76: 1 -4.53,-0.635; 2 -4.53,-1.905; 3 -4.53,-3.175; 9 4.53,-3.175; 10 4.53,-1.905; 11 4.53,-0.635; 12 4.53,0.635; 13 4.53,1.905; 19 -4.53,1.905; 20 -4.53,0.635
smd 0.76 x 1.8: 4 -2.54,-4.47; 5 -1.27,-4.47; 6 0,-4.47; 7 1.27,-4.47; 8 2.54,-4.47; 14 2.54,3.2; 15 1.27,3.2; 16 0,3.2; 17 -1.27,3.2; 18 -2.54,3.2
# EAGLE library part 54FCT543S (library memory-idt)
MEMORY

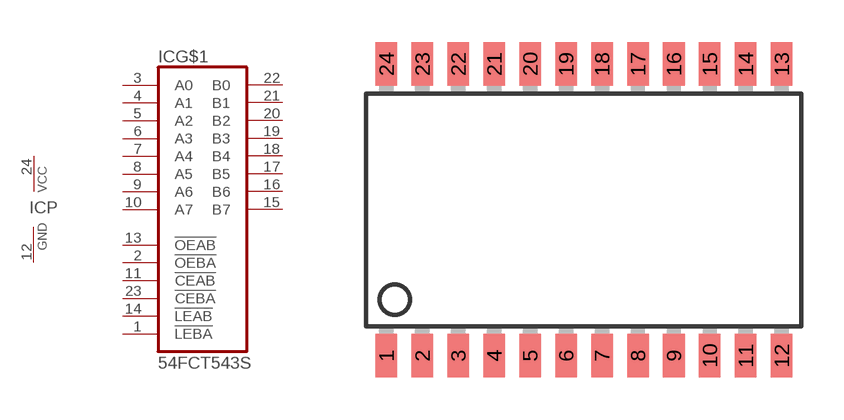
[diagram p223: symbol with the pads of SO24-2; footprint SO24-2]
Designator prefix IC; gates G$1=543 P=VCCGND

## 54FCT543S (OC_FARNELL: unknown; OC_NEWARK: unknown)  [SO24-2]
1  G$1:!LEBA  in
2  G$1:!OEBA  in
3  G$1:A0
4  G$1:A1
5  G$1:A2
6  G$1:A3
7  G$1:A4
8  G$1:A5
9  G$1:A6
10  G$1:A7
11  G$1:!CEAB  in
12  P:GND  pwr
13  G$1:!OEAB  in
14  G$1:!LEAB  in
15  G$1:B7
16  G$1:B6
17  G$1:B5
18  G$1:B4
19  G$1:B3
20  G$1:B2
21  G$1:B1
22  G$1:B0
23  G$1:!CEBA  in
24  P:VCC  pwr

## Footprint SO24-2 (pad centres in mm)
Small Outline Package
smd 0.762 x 1.524: 1 -6.985,-5.156; 2 -5.715,-5.156; 3 -4.445,-5.156; 4 -3.175,-5.156; 5 -1.905,-5.156; 6 -0.635,-5.156; 7 0.635,-5.156; 8 1.905,-5.156; 9 3.175,-5.156; 10 4.445,-5.156; 11 5.715,-5.156; 12 6.985,-5.156; 13 6.985,5.156; 14 5.715,5.156; 15 4.445,5.156; 16 3.175,5.156; 17 1.905,5.156; 18 0.635,5.156; 19 -0.635,5.156; 20 -1.905,5.156; 21 -3.175,5.156; 22 -4.445,5.156; 23 -5.715,5.156; 24 -6.985,5.156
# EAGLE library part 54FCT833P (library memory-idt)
MEMORY

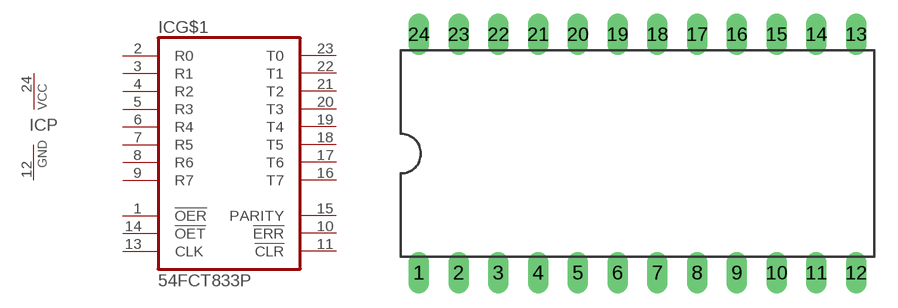
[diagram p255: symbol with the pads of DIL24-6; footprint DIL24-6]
Designator prefix IC; gates G$1=833 P=VCCGND

## 54FCT833P (OC_FARNELL: unknown; OC_NEWARK: unknown)  [DIL24-6]
1  G$1:!OER  in
2  G$1:R0
3  G$1:R1
4  G$1:R2
5  G$1:R3
6  G$1:R4
7  G$1:R5
8  G$1:R6
9  G$1:R7
10  G$1:!ERR  out
11  G$1:!CLR  out
12  P:GND  pwr
13  G$1:CLK  in
14  G$1:!OET  in
15  G$1:PARITY
16  G$1:T7
17  G$1:T6
18  G$1:T5
19  G$1:T4
20  G$1:T3
21  G$1:T2
22  G$1:T1
23  G$1:T0
24  P:VCC  pwr

## Footprint DIL24-6 (pad centres in mm)
Dual In Line Package 0.6 inch
drill 0.813 long: 1 -13.97,-7.62; 2 -11.43,-7.62; 3 -8.89,-7.62; 4 -6.35,-7.62; 5 -3.81,-7.62; 6 -1.27,-7.62; 7 1.27,-7.62; 8 3.81,-7.62; 9 6.35,-7.62; 10 8.89,-7.62; 11 11.43,-7.62; 12 13.97,-7.62; 13 13.97,7.62; 14 11.43,7.62; 15 8.89,7.62; 16 6.35,7.62; 17 3.81,7.62; 18 1.27,7.62; 19 -1.27,7.62; 20 -3.81,7.62; 21 -6.35,7.62; 22 -8.89,7.62; 23 -11.43,7.62; 24 -13.97,7.62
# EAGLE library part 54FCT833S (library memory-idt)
MEMORY

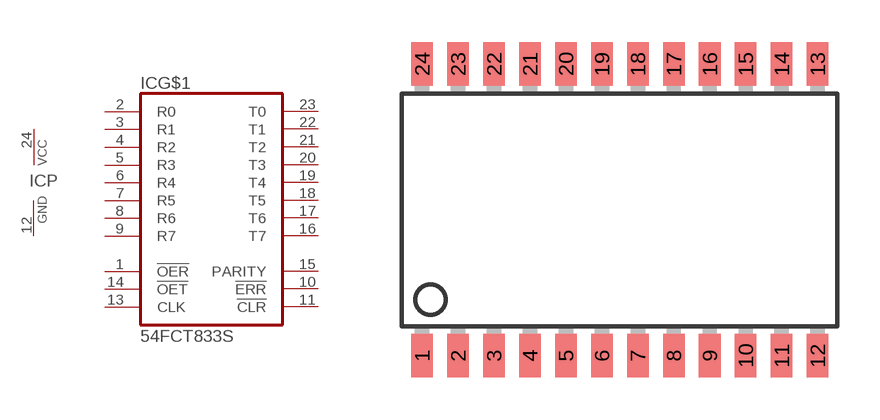
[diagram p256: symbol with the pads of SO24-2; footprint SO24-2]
Designator prefix IC; gates G$1=833 P=VCCGND

## 54FCT833S (OC_FARNELL: unknown; OC_NEWARK: unknown)  [SO24-2]
1  G$1:!OER  in
2  G$1:R0
3  G$1:R1
4  G$1:R2
5  G$1:R3
6  G$1:R4
7  G$1:R5
8  G$1:R6
9  G$1:R7
10  G$1:!ERR  out
11  G$1:!CLR  out
12  P:GND  pwr
13  G$1:CLK  in
14  G$1:!OET  in
15  G$1:PARITY
16  G$1:T7
17  G$1:T6
18  G$1:T5
19  G$1:T4
20  G$1:T3
21  G$1:T2
22  G$1:T1
23  G$1:T0
24  P:VCC  pwr

## Footprint SO24-2 (pad centres in mm)
Small Outline Package
smd 0.762 x 1.524: 1 -6.985,-5.156; 2 -5.715,-5.156; 3 -4.445,-5.156; 4 -3.175,-5.156; 5 -1.905,-5.156; 6 -0.635,-5.156; 7 0.635,-5.156; 8 1.905,-5.156; 9 3.175,-5.156; 10 4.445,-5.156; 11 5.715,-5.156; 12 6.985,-5.156; 13 6.985,5.156; 14 5.715,5.156; 15 4.445,5.156; 16 3.175,5.156; 17 1.905,5.156; 18 0.635,5.156; 19 -0.635,5.156; 20 -1.905,5.156; 21 -3.175,5.156; 22 -4.445,5.156; 23 -5.715,5.156; 24 -6.985,5.156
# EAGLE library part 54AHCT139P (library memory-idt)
MEMORY

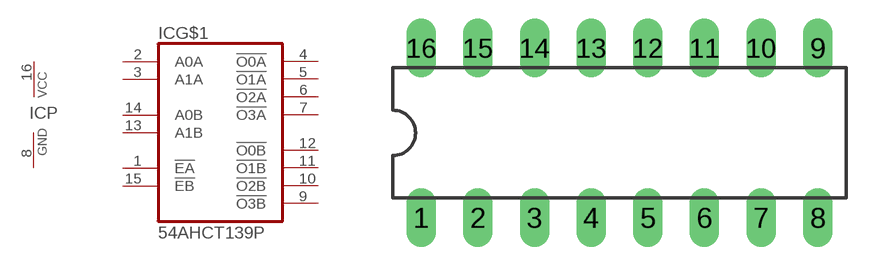
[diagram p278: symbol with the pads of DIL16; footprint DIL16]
Designator prefix IC; gates G$1=139 P=VCCGND

## 54AHCT139P (OC_FARNELL: unknown; OC_NEWARK: unknown)  [DIL16]
1  G$1:!EA  in
2  G$1:A0A  in
3  G$1:A1A  in
4  G$1:!O0A  out
5  G$1:!O1A  out
6  G$1:!O2A  out
7  G$1:!O3A  out
8  P:GND  pwr
9  G$1:!O3B  out
10  G$1:!O2B  out
11  G$1:!O1B  out
12  G$1:!O0B  out
13  G$1:A1B  in
14  G$1:A0B  in
15  G$1:!EB  in
16  P:VCC  pwr

## Footprint DIL16 (pad centres in mm)
Dual In Line Package
drill 0.813 long: 1 -8.89,-3.81; 2 -6.35,-3.81; 3 -3.81,-3.81; 4 -1.27,-3.81; 5 1.27,-3.81; 6 3.81,-3.81; 7 6.35,-3.81; 8 8.89,-3.81; 9 8.89,3.81; 10 6.35,3.81; 11 3.81,3.81; 12 1.27,3.81; 13 -1.27,3.81; 14 -3.81,3.81; 15 -6.35,3.81; 16 -8.89,3.81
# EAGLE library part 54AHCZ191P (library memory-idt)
MEMORY

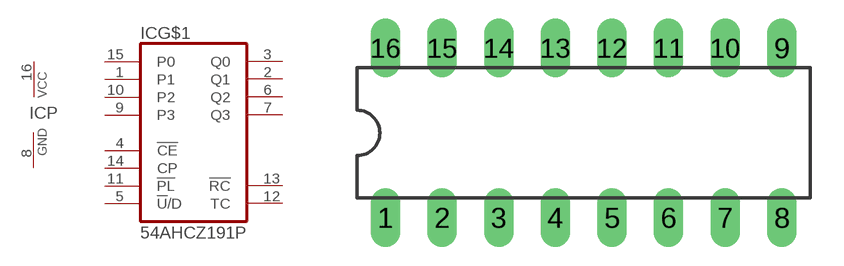
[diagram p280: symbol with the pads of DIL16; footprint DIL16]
Designator prefix IC; gates G$1=191 P=VCCGND

## 54AHCZ191P (OC_FARNELL: unknown; OC_NEWARK: unknown)  [DIL16]
1  G$1:P1  in
2  G$1:Q1  out
3  G$1:Q0  out
4  G$1:!CE  in
5  G$1:!U!/D  in
6  G$1:Q2  out
7  G$1:Q3  out
8  P:GND  pwr
9  G$1:P3  in
10  G$1:P2  in
11  G$1:!PL  in
12  G$1:TC  out
13  G$1:!RC  out
14  G$1:CP  in
15  G$1:P0  in
16  P:VCC  pwr

## Footprint DIL16 (pad centres in mm)
Dual In Line Package
drill 0.813 long: 1 -8.89,-3.81; 2 -6.35,-3.81; 3 -3.81,-3.81; 4 -1.27,-3.81; 5 1.27,-3.81; 6 3.81,-3.81; 7 6.35,-3.81; 8 8.89,-3.81; 9 8.89,3.81; 10 6.35,3.81; 11 3.81,3.81; 12 1.27,3.81; 13 -1.27,3.81; 14 -3.81,3.81; 15 -6.35,3.81; 16 -8.89,3.81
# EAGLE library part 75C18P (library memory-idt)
MEMORY

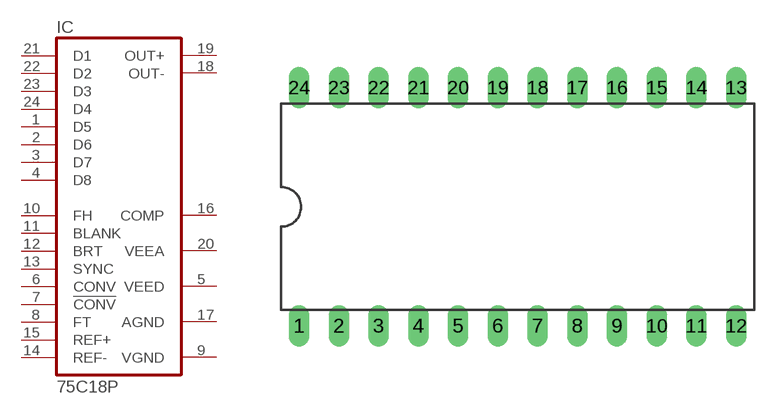
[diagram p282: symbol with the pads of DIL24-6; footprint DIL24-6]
Designator prefix IC

## 75C18P (OC_FARNELL: unknown; OC_NEWARK: unknown)  [DIL24-6]
1  D5  in
2  D6  in
3  D7  in
4  D8  in
5  VEED  pwr
6  CONV  in
7  !CONV  in
8  FT  in
9  VGND  pwr
10  FH  in
11  BLANK  in
12  BRT  in
13  SYNC  in
14  REF-  in
15  REF+  in
16  COMP  pas
17  AGND  pwr
18  OUT-  out
19  OUT+  out
20  VEEA  pwr
21  D1  in
22  D2  in
23  D3  in
24  D4  in

## Footprint DIL24-6 (pad centres in mm)
Dual In Line Package 0.6 inch
drill 0.813 long: 1 -13.97,-7.62; 2 -11.43,-7.62; 3 -8.89,-7.62; 4 -6.35,-7.62; 5 -3.81,-7.62; 6 -1.27,-7.62; 7 1.27,-7.62; 8 3.81,-7.62; 9 6.35,-7.62; 10 8.89,-7.62; 11 11.43,-7.62; 12 13.97,-7.62; 13 13.97,7.62; 14 11.43,7.62; 15 8.89,7.62; 16 6.35,7.62; 17 3.81,7.62; 18 1.27,7.62; 19 -1.27,7.62; 20 -3.81,7.62; 21 -6.35,7.62; 22 -8.89,7.62; 23 -11.43,7.62; 24 -13.97,7.62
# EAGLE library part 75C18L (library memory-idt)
MEMORY

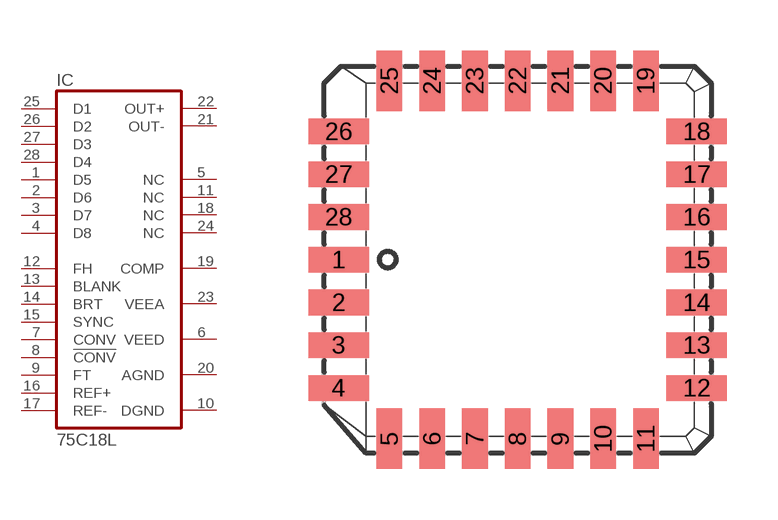
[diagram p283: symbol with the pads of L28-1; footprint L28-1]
Designator prefix IC

## 75C18L (OC_FARNELL: unknown; OC_NEWARK: unknown)  [L28-1]
1  D5  in
2  D6  in
3  D7  in
4  D8  in
5  NC  nc
6  VEED  pwr
7  CONV  in
8  !CONV  in
9  FT  in
10  DGND  pwr
11  NC  nc
12  FH  in
13  BLANK  in
14  BRT  in
15  SYNC  in
16  REF+  in
17  REF-  in
18  NC  nc
19  COMP  pas
20  AGND  pwr
21  OUT-  out
22  OUT+  out
23  VEEA  pwr
24  NC  nc
25  D1  in
26  D2  in
27  D3  in
28  D4  in

## Footprint L28-1 (pad centres in mm)
PLASTIC LEADED CHIP CARRIER square
smd 1.8 x 0.76: 1 -5.32,0; 2 -5.32,-1.27; 3 -5.32,-2.54; 4 -5.32,-3.81; 12 5.32,-3.81; 13 5.32,-2.54; 14 5.32,-1.27; 15 5.32,0; 16 5.32,1.27; 17 5.32,2.54; 18 5.32,3.81; 26 -5.32,3.81; 27 -5.32,2.54; 28 -5.32,1.27
smd 0.76 x 1.8: 5 -3.81,-5.32; 6 -2.54,-5.32; 7 -1.27,-5.32; 8 0,-5.32; 9 1.27,-5.32; 10 2.54,-5.32; 11 3.81,-5.32; 19 3.81,5.32; 20 2.54,5.32; 21 1.27,5.32; 22 0,5.32; 23 -1.27,5.32; 24 -2.54,5.32; 25 -3.81,5.32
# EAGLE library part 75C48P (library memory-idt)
MEMORY

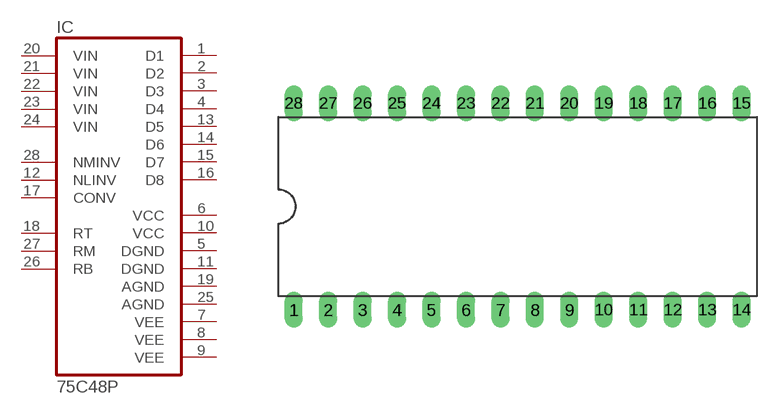
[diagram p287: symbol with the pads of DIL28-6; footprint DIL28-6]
Designator prefix IC

## 75C48P (OC_FARNELL: unknown; OC_NEWARK: unknown)  [DIL28-6]
1  D1  out
2  D2  out
3  D3  out
4  D4  out
5  DGND  pwr
6  VCC  pwr
7  VEE  pwr
8  VEE  pwr
9  VEE  pwr
10  VCC  pwr
11  DGND  pwr
12  NLINV  in
13  D5  out
14  D6  out
15  D7  out
16  D8  out
17  CONV  in
18  RT  in
19  AGND  pwr
20  VIN  in
21  VIN  in
22  VIN  in
23  VIN  in
24  VIN  in
25  AGND  pwr
26  RB  in
27  RM  in
28  NMINV  in

## Footprint DIL28-6 (pad centres in mm)
Dual In Line Package 0.6 inch
drill 0.813 long: 1 -16.51,-7.62; 2 -13.97,-7.62; 3 -11.43,-7.62; 4 -8.89,-7.62; 5 -6.35,-7.62; 6 -3.81,-7.62; 7 -1.27,-7.62; 8 1.27,-7.62; 9 3.81,-7.62; 10 6.35,-7.62; 11 8.89,-7.62; 12 11.43,-7.62; 13 13.97,-7.62; 14 16.51,-7.62; 15 16.51,7.62; 16 13.97,7.62; 17 11.43,7.62; 18 8.89,7.62; 19 6.35,7.62; 20 3.81,7.62; 21 1.27,7.62; 22 -1.27,7.62; 23 -3.81,7.62; 24 -6.35,7.62; 25 -8.89,7.62; 26 -11.43,7.62; 27 -13.97,7.62; 28 -16.51,7.62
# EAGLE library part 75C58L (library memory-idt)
MEMORY

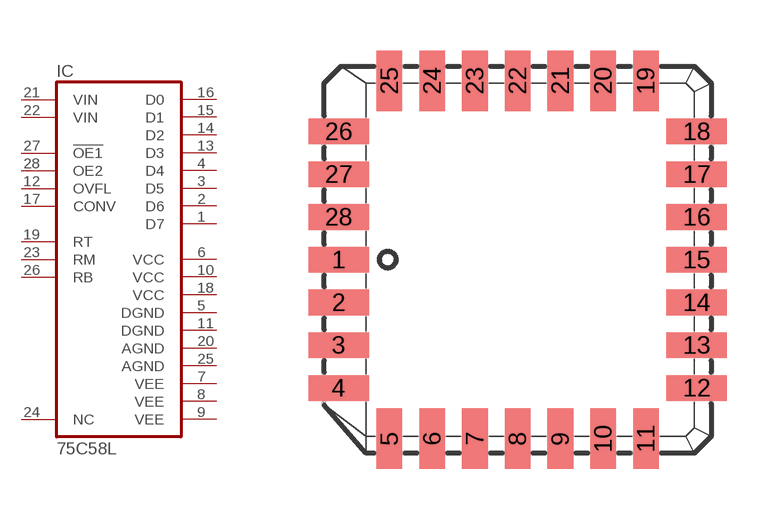
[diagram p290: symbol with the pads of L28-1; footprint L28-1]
Designator prefix IC

## 75C58L (OC_FARNELL: unknown; OC_NEWARK: unknown)  [L28-1]
1  D7  out
2  D6  out
3  D5  out
4  D4  out
5  DGND  pwr
6  VCC  pwr
7  VEE  pwr
8  VEE  pwr
9  VEE  pwr
10  VCC  pwr
11  DGND  pwr
12  OVFL  in
13  D3  out
14  D2  out
15  D1  out
16  D0  out
17  CONV  in
18  VCC  pwr
19  RT  in
20  AGND  pwr
21  VIN  in
22  VIN  in
23  RM  in
24  NC  nc
25  AGND  pwr
26  RB  in
27  !OE1  in
28  OE2  in

## Footprint L28-1 (pad centres in mm)
PLASTIC LEADED CHIP CARRIER square
smd 1.8 x 0.76: 1 -5.32,0; 2 -5.32,-1.27; 3 -5.32,-2.54; 4 -5.32,-3.81; 12 5.32,-3.81; 13 5.32,-2.54; 14 5.32,-1.27; 15 5.32,0; 16 5.32,1.27; 17 5.32,2.54; 18 5.32,3.81; 26 -5.32,3.81; 27 -5.32,2.54; 28 -5.32,1.27
smd 0.76 x 1.8: 5 -3.81,-5.32; 6 -2.54,-5.32; 7 -1.27,-5.32; 8 0,-5.32; 9 1.27,-5.32; 10 2.54,-5.32; 11 3.81,-5.32; 19 3.81,5.32; 20 2.54,5.32; 21 1.27,5.32; 22 0,5.32; 23 -1.27,5.32; 24 -2.54,5.32; 25 -3.81,5.32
